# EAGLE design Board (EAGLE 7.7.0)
Assembly variants: PASTE

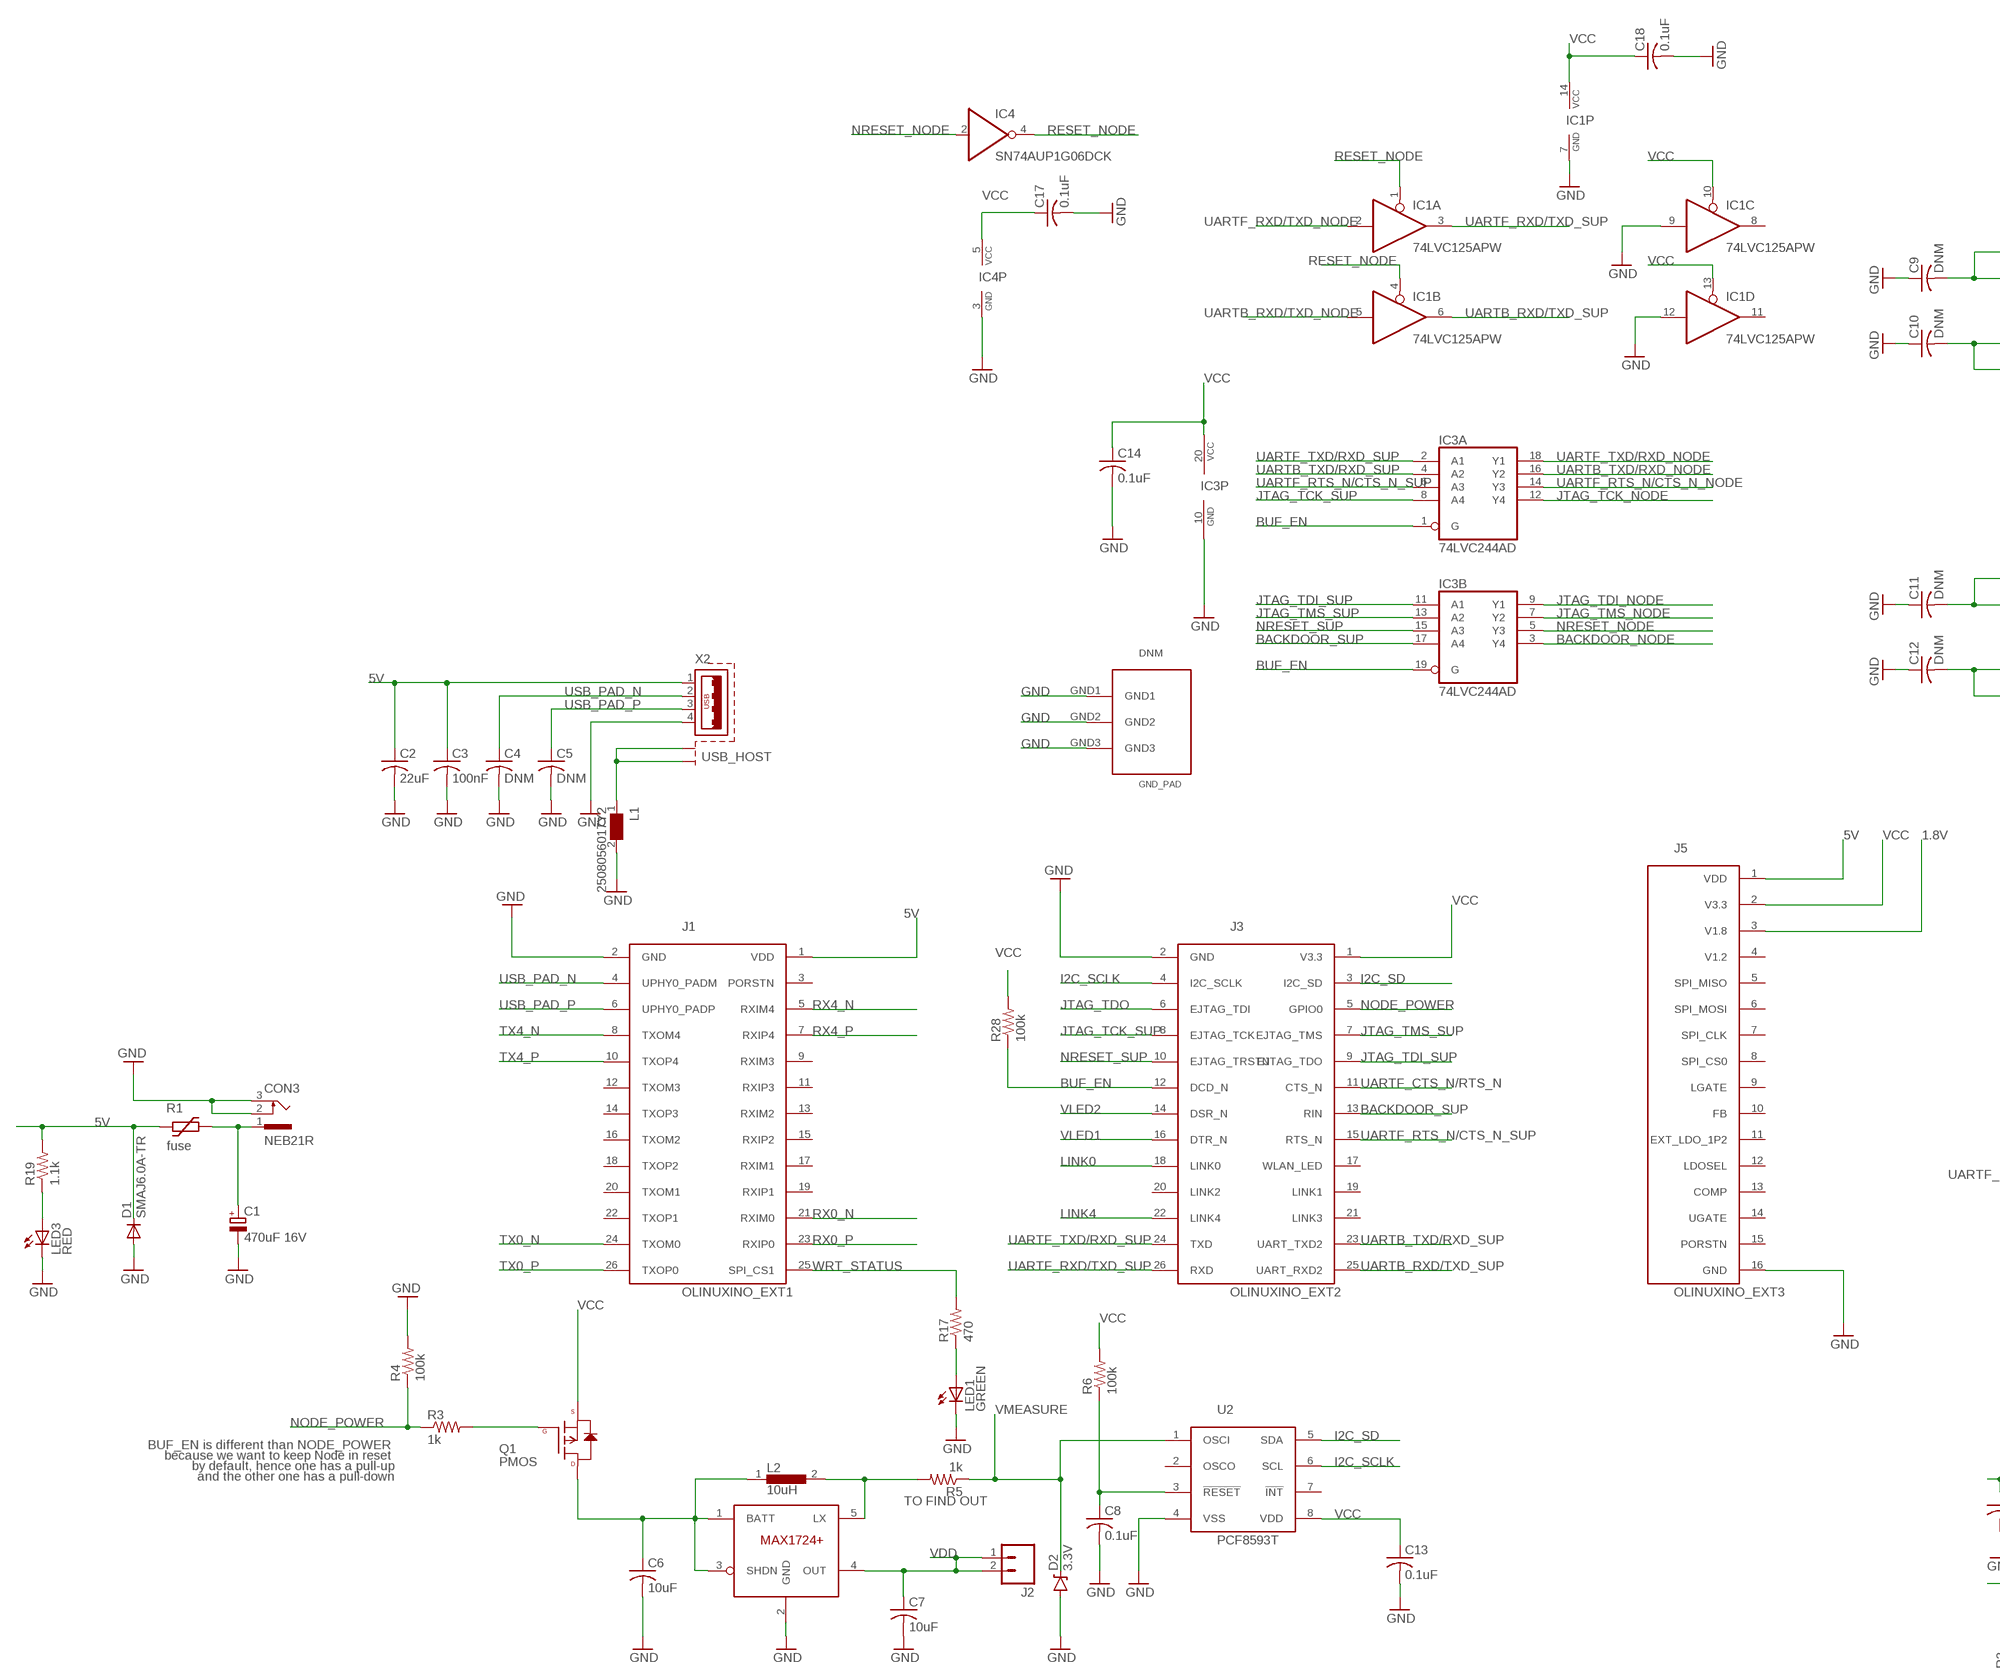
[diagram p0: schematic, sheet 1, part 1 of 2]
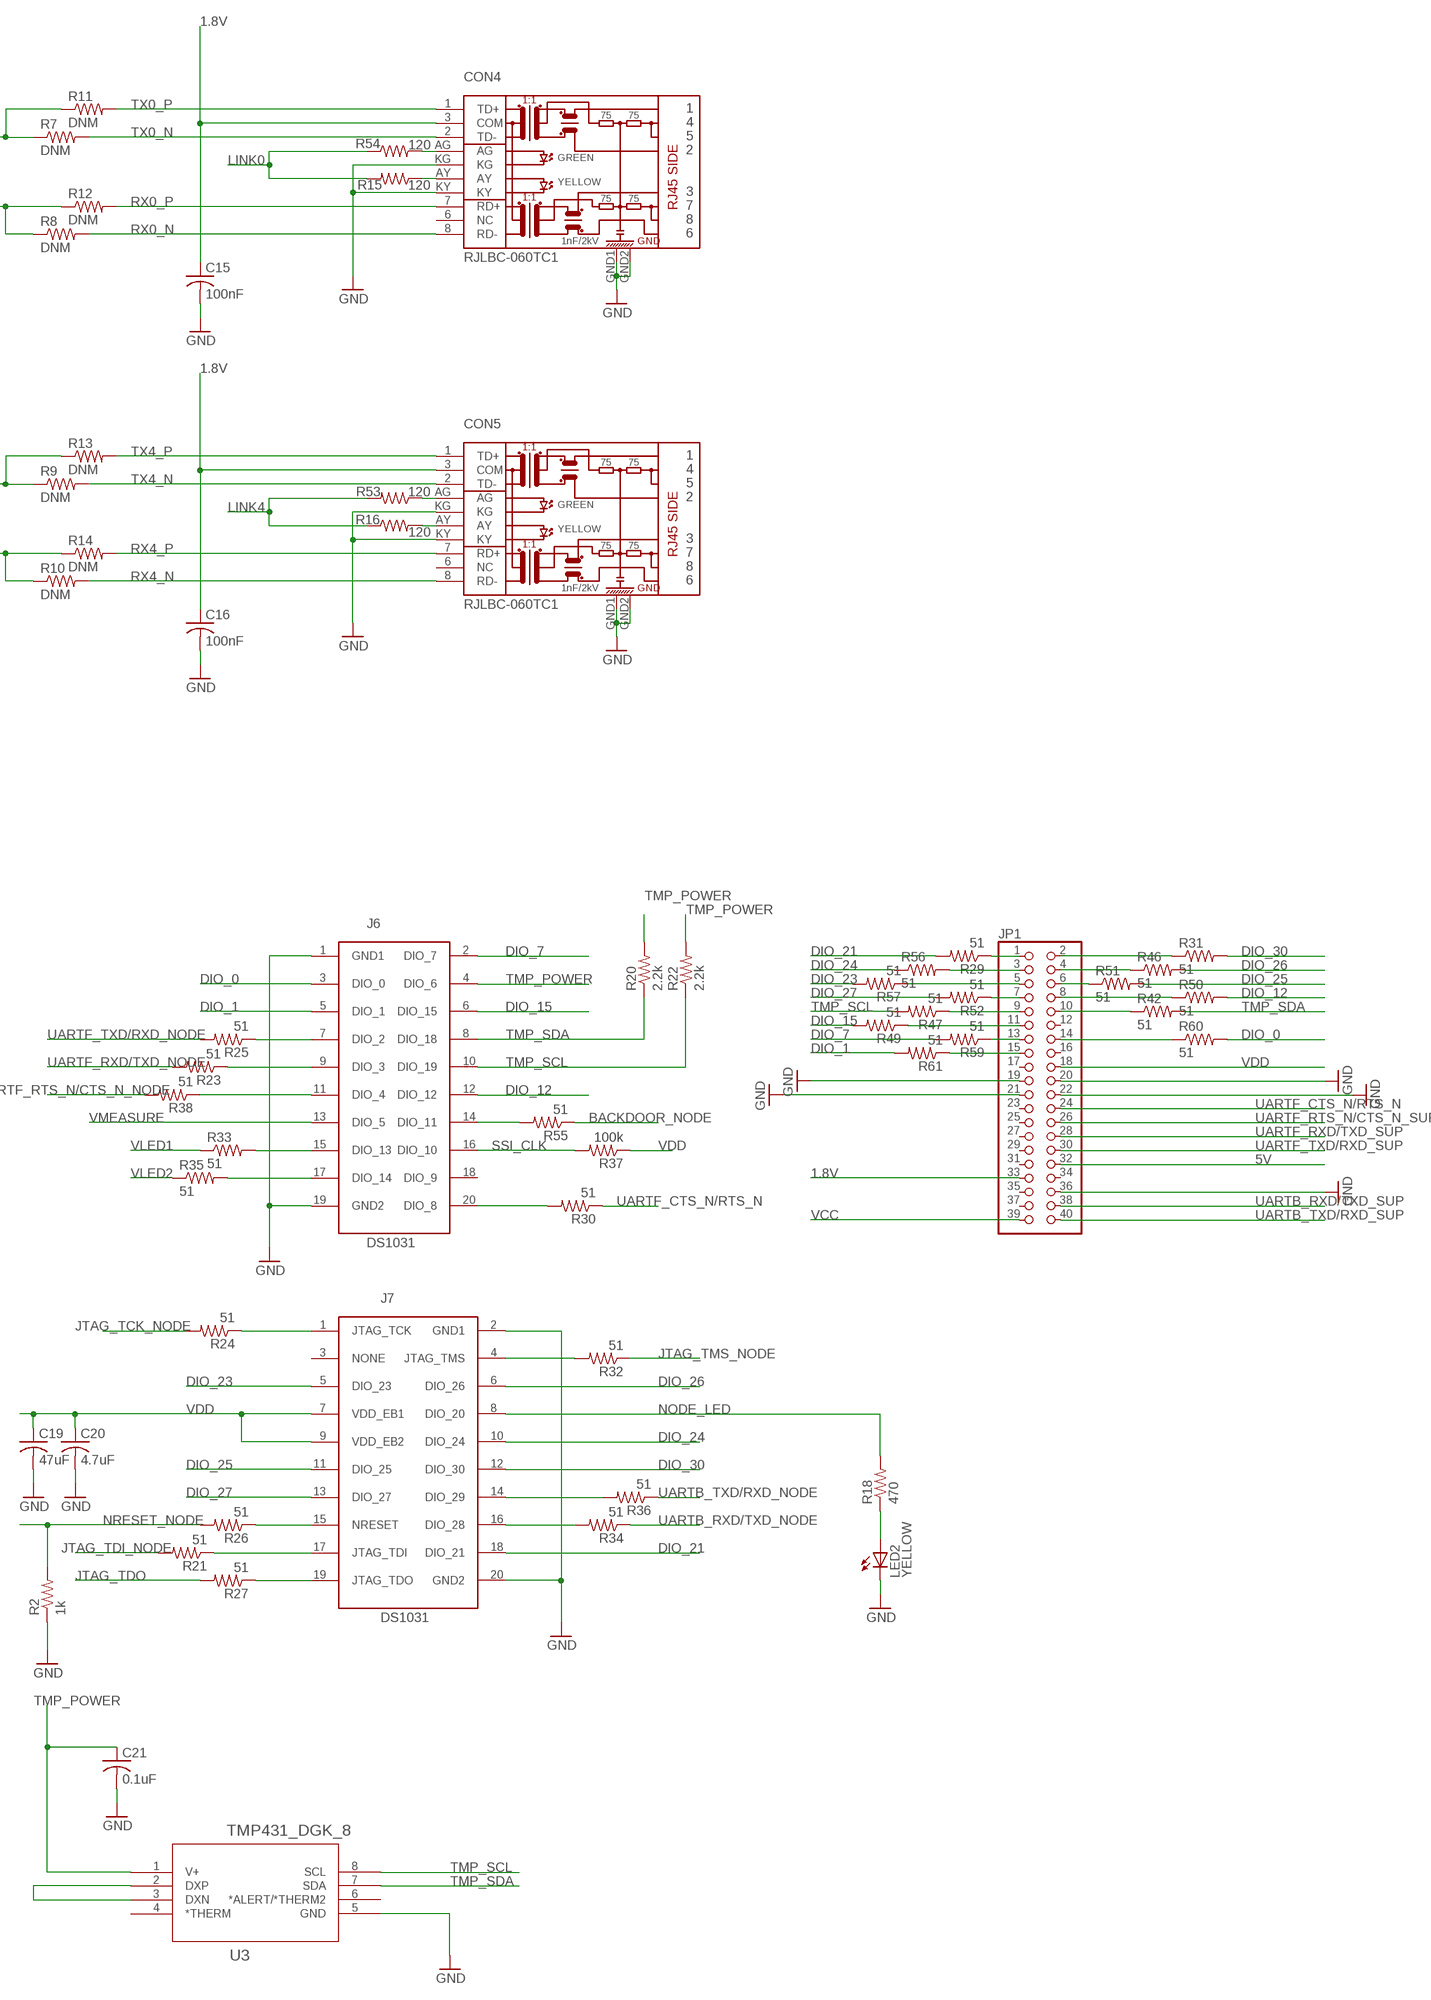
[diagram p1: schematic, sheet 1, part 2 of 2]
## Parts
C1  470uF 16V  CPOL-EU153CLV-0810  [153CLV-0810]
C2  22uF  C-USC0603  [C0603]
C3  100nF  C-USC0603  [C0603]
C4  DNM  C-USC0603  [C0603]
C5  DNM  C-USC0603  [C0603]
C6  10uF  C-USC0603  [C0603]
C7  10uF  C-USC0603  [C0603]
C8  0.1uF  C-USC0603  [C0603]
C9  DNM  C-USC0603  [C0603]
C10  DNM  C-USC0603  [C0603]
C11  DNM  C-USC0603  [C0603]
C12  DNM  C-USC0603  [C0603]
C13  0.1uF  C-USC0603  [C0603]
C14  0.1uF  C-USC0603  [C0603]
C15  100nF  C-USC0603  [C0603]
C16  100nF  C-USC0603  [C0603]
C17  0.1uF  C-USC0603  [C0603]
C18  0.1uF  C-USC0603  [C0603]
C19  47uF  C-USC1206  [C1206]
C20  4.7uF  C-USC0603  [C0603]
C21  0.1uF  C-USC0603  [C0603]
CON3  NEB21R  [NEB21R]
CON4  RJLBC-060TC1  RJLBC-060TC1_GND  [RJLBC-060TC1]
CON5  RJLBC-060TC1  RJLBC-060TC1_GND  [RJLBC-060TC1]
D1  SMAJ6.0A-TR  DIODE-DO214AC  [DO214AC]
D2  3.3V  DIODE-ZENER3.3V  [SOD-323]
GND_PAD  DNM  GND_PAD  [GND_PAD]  (not fitted in variant PASTE)
IC1  74LVC125APW  74ABT125PW  [TSSOP14]
IC3  74LVC244AD  74LS244DW  [SO20W]
IC4  SN74AUP1G06DCK  74AUC1G06DCK  [SC70-5]
J1  OLINUXINO_EXT1  [SSW-113-02-S-D]
J2  M02PTH  [1X02]
J3  OLINUXINO_EXT2  [SSW-113-02-S-D]
J5  OLINUXINO_EXT3  [SSW-116-02-S-S]
J6  DS1031  CC2650_EM1  [DS1031-08-2*10P8BS-4-1]
J7  DS1031  CC2650_EM2  [DS1031-08-2*10P8BS-4-1]
JP1  PINHD-2X20-BIG  [2X20-BIG]
L1  2508056017Y2  WE-CBF_0805  [0805]
L2  10uH  CR32  [CR32]
LED1  GREEN  LED3MM  [LED3MM]
LED2  YELLOW  LED3MM  [LED3MM]
LED3  RED  LED3MM  [LED3MM]
Q1  PMOS  P-CHANNEL-MOSFET  [SOT23-3]
R1  fuse  SD125-06  [1812]
R2  1k  RESISTOR0603  [0603-RES]
R3  1k  RESISTOR0603  [0603-RES]
R4  100k  RESISTOR0603  [0603-RES]
R5  1k  RESISTOR0603  [0603-RES]
R6  100k  RESISTOR0603  [0603-RES]
R7  DNM  RESISTOR0603  [0603-RES]
R8  DNM  RESISTOR0603  [0603-RES]
R9  DNM  RESISTOR0603  [0603-RES]
R10  DNM  RESISTOR0603  [0603-RES]
R11  DNM  RESISTOR0603  [0603-RES]
R12  DNM  RESISTOR0603  [0603-RES]
R13  DNM  RESISTOR0603  [0603-RES]
R14  DNM  RESISTOR0603  [0603-RES]
R15  120  RESISTOR0603  [0603-RES]
R16  120  RESISTOR0603  [0603-RES]
R17  470  RESISTOR0603  [0603-RES]
R18  470  RESISTOR0603  [0603-RES]
R19  1.1k  RESISTOR0603  [0603-RES]
R20  2.2k  RESISTOR0603  [0603-RES]
R21  51  RESISTOR0603  [0603-RES]
R22  2.2k  RESISTOR0603  [0603-RES]
R23  51  RESISTOR0603  [0603-RES]
R24  51  RESISTOR0603  [0603-RES]
R25  51  RESISTOR0603  [0603-RES]
R26  51  RESISTOR0603  [0603-RES]
R27  51  RESISTOR0603  [0603-RES]
R28  100k  RESISTOR0603  [0603-RES]
R29  51  RESISTOR0603  [0603-RES]
R30  51  RESISTOR0603  [0603-RES]
R31  51  RESISTOR0603  [0603-RES]
R32  51  RESISTOR0603  [0603-RES]
R33  51  RESISTOR0603  [0603-RES]
R34  51  RESISTOR0603  [0603-RES]
R35  51  RESISTOR0603  [0603-RES]
R36  51  RESISTOR0603  [0603-RES]
R37  100k  RESISTOR0603  [0603-RES]
R38  51  RESISTOR0603  [0603-RES]
R42  51  RESISTOR0603  [0603-RES]
R46  51  RESISTOR0603  [0603-RES]
R47  51  RESISTOR0603  [0603-RES]
R49  51  RESISTOR0603  [0603-RES]
R50  51  RESISTOR0603  [0603-RES]
R51  51  RESISTOR0603  [0603-RES]
R52  51  RESISTOR0603  [0603-RES]
R53  120  RESISTOR0603  [0603-RES]
R54  120  RESISTOR0603  [0603-RES]
R55  51  RESISTOR0603  [0603-RES]
R56  51  RESISTOR0603  [0603-RES]
R57  51  RESISTOR0603  [0603-RES]
R59  51  RESISTOR0603  [0603-RES]
R60  51  RESISTOR0603  [0603-RES]
R61  51  RESISTOR0603  [0603-RES]
U1  MAX1724  [SOT23-5L]
U2  PCF8593T  [SO-08]
U3  TMP431_DGK_8  [DGK8]
X2  USB_HOST  TUEA4F2S0BHT  [TUEA4F2S0BHT]

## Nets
1.8V [supply]: C15.1 C16.1 CON4.3(COM) CON5.3(COM) J5.3(V1.8) JP1.33
5V [supply]: C2.1 C3.1 D1.C J1.1(VDD) J5.1(VDD) JP1.32 R1.P$1 R19.2 X2.1(VCC)
BACKDOOR_NODE: IC3.3(B:Y4) R55.1
BACKDOOR_SUP: IC3.17(B:A4) J3.13(RIN)
BATT [supply]: C6.1 L2.1 Q1.3(D) U1.1(BATT) U1.3(SHDN)
BUF_EN: IC3.1(A:G) IC3.19(B:G) J3.12(DCD_N) R28.1
COUNTER [supply]: L2.2 R5.2 U1.5(LX)
DIO_0: J6.3(DIO_0) R60.2
DIO_1: J6.5(DIO_1) R61.2
DIO_7: J6.2(DIO_7) R59.2
DIO_12: J6.12(DIO_12) R50.2
DIO_15: J6.6(DIO_15) R49.2
DIO_21: J7.18(DIO_21) R29.2
DIO_23: J7.5(DIO_23) R57.2
DIO_24: J7.10(DIO_24) R56.1
DIO_25: J7.11(DIO_25) R51.2
DIO_26: J7.6(DIO_26) R46.2
DIO_27: J7.13(DIO_27) R52.2
DIO_30: J7.12(DIO_30) R31.2
GND [supply]: C1.- C2.2 C3.2 C4.2 C5.2 C6.2 C7.2 C8.2 C9.1 C10.1 C11.1 C12.1 C13.2 C14.2 C15.2 C16.2 C17.2 C18.2 C19.2 C20.2 C21.2 CON3.2 CON3.3 CON4.GND1 CON4.GND2 CON4.KG CON4.KY CON5.GND1 CON5.GND2 CON5.KG CON5.KY D1.A D2.A GND_PAD.GND1 GND_PAD.GND2 GND_PAD.GND3 IC1.7(P:GND) IC1.9(C:I) IC1.12(D:I) IC3.10(P:GND) IC4.3(GND) J1.2(GND) J3.2(GND) J5.16(GND) J6.1(GND1) J6.19(GND2) J7.2(GND1) J7.20(GND2) JP1.19 JP1.20 JP1.21 JP1.22 JP1.36 L1.2 LED1.K(C) LED2.K(C) LED3.K(C) R2.1 R4.2 U1.2(GND) U2.4(VSS) U3.5(GND) X2.4(GND)
I2C_SCLK: J3.4(I2C_SCLK) U2.6(SCL)
I2C_SD: J3.3(I2C_SD) U2.5(SDA)
JTAG_TCK_NODE: IC3.12(A:Y4) R24.2
JTAG_TCK_SUP: IC3.8(A:A4) J3.8(EJTAG_TCK)
JTAG_TDI_NODE: IC3.9(B:Y1) R21.2
JTAG_TDI_SUP: IC3.11(B:A1) J3.9(EJTAG_TDO)
JTAG_TDO: J3.6(EJTAG_TDI) R27.2
JTAG_TMS_NODE: IC3.7(B:Y2) R32.1
JTAG_TMS_SUP: IC3.13(B:A2) J3.7(EJTAG_TMS)
LINK0: J3.18(LINK0) R15.2 R54.1
LINK4: J3.22(LINK4) R16.1 R53.2
N$1: CON4.AG R54.2
N$2: Q1.1(G) R3.2
N$3: C12.2 R10.1 R14.1
N$4: C11.2 R9.1 R13.1
N$13: CON5.AY R16.2
N$14 [supply]: L1.1 X2.S1 X2.S2
N$15: J7.4(JTAG_TMS) R32.2
N$18: J7.1(JTAG_TCK) R24.1
N$19: C10.2 R8.1 R12.1
N$20: J7.15(NRESET) R26.1
N$21: C9.2 R7.1 R11.1
N$22: J7.17(JTAG_TDI) R21.1
N$23: J7.19(JTAG_TDO) R27.1
N$24: J6.7(DIO_2) R25.1
N$25: J6.9(DIO_3) R23.1
N$26: JP1.1 R29.1
N$27: CON4.AY R15.1
N$28: J6.20(DIO_8) R30.2
N$29: LED1.A R17.1
N$30: LED2.A R18.1
N$31: J6.14(DIO_11) R55.2
N$32: C1.+ CON3.1 R1.P$2
N$33: CON5.AG R53.1
N$34: C8.1 R6.1 U2.3(!RESET)
N$35: J6.15(DIO_13) R33.2
N$36: JP1.2 R31.1
N$37: JP1.3 R56.2
N$38: J6.17(DIO_14) R35.2
N$40: JP1.4 R46.1
N$41: JP1.5 R57.1
N$42: JP1.6 R51.1
N$43: JP1.7 R52.1
N$44: JP1.8 R50.1
N$45: JP1.9 R47.1
N$46: JP1.10 R42.1
N$47: JP1.11 R49.1
N$49: U3.2(DXP) U3.3(DXN)
N$50: LED3.A R19.1
N$65: JP1.13 R59.1
N$66: J7.14(DIO_29) R36.2
N$67: J7.16(DIO_28) R34.2
N$68: JP1.14 R60.1
N$69: JP1.15 R61.1
N$72: J6.11(DIO_4) R38.1
NODE_LED: J7.8(DIO_20) R18.2
NODE_POWER: J3.5(GPIO0) R3.1 R4.1
NRESET_NODE: IC3.5(B:Y3) IC4.2(I) R2.2 R26.2
NRESET_SUP: IC3.15(B:A3) J3.10(EJTAG_TRSTN)
RESET_NODE: IC1.1(A:OE) IC1.4(B:OE) IC4.4(O)
RX0_N: CON4.8(RD-) J1.21(RXIM0) R8.2
RX0_P: CON4.7(RD+) J1.23(RXIP0) R12.2
RX4_N: CON5.8(RD-) J1.5(RXIM4) R10.2
RX4_P: CON5.7(RD+) J1.7(RXIP4) R14.2
SSI_CLK: J6.16(DIO_10) R37.2
TMP_POWER [supply]: C21.1 J6.4(DIO_6) R20.2 R22.2 U3.1(V+)
TMP_SCL: J6.10(DIO_19) R22.1 R47.2 U3.8(SCL)
TMP_SDA: J6.8(DIO_18) R20.1 R42.2 U3.7(SDA)
TX0_N: CON4.2(TD-) J1.24(TXOM0) R7.2
TX0_P: CON4.1(TD+) J1.26(TXOP0) R11.2
TX4_N: CON5.2(TD-) J1.8(TXOM4) R9.2
TX4_P: CON5.1(TD+) J1.10(TXOP4) R13.2
UARTB_RXD/TXD_NODE: IC1.5(B:I) R34.1
UARTB_RXD/TXD_SUP: IC1.6(B:O) J3.25(UART_RXD2) JP1.38
UARTB_TXD/RXD_NODE: IC3.16(A:Y2) R36.1
UARTB_TXD/RXD_SUP: IC3.4(A:A2) J3.23(UART_TXD2) JP1.40
UARTF_CTS_N/RTS_N: J3.11(CTS_N) JP1.24 R30.1
UARTF_RTS_N/CTS_N_NODE: IC3.14(A:Y3) R38.2
UARTF_RTS_N/CTS_N_SUP: IC3.6(A:A3) J3.15(RTS_N) JP1.26
UARTF_RXD/TXD_NODE: IC1.2(A:I) R23.2
UARTF_RXD/TXD_SUP: IC1.3(A:O) J3.26(RXD) JP1.28
UARTF_TXD/RXD_NODE: IC3.18(A:Y1) R25.2
UARTF_TXD/RXD_SUP: IC3.2(A:A1) J3.24(TXD) JP1.30
USB_PAD_N: C4.1 J1.4(UPHY0_PADM) X2.2(D-)
USB_PAD_P: C5.1 J1.6(UPHY0_PADP) X2.3(D+)
VCC [supply]: C13.1 C14.1 C17.1 C18.1 IC1.10(C:OE) IC1.13(D:OE) IC1.14(P:VCC) IC3.20(P:VCC) IC4.5(VCC) J3.1(V3.3) J5.2(V3.3) JP1.39 Q1.2(S) R6.2 R28.2 U2.8(VDD)
VDD [supply]: C7.1 C19.1 C20.1 J2.1 J2.2 J7.7(VDD_EB1) J7.9(VDD_EB2) JP1.18 R37.1 U1.4(OUT)
VLED1: J3.16(DTR_N) R33.1
VLED2: J3.14(DSR_N) R35.1
VMEASURE: D2.C J6.13(DIO_5) R5.1 U2.1(OSCI)
WRT_STATUS: J1.25(SPI_CS1) R17.2
Unconnected: CON4.6(NC) CON5.6(NC) IC1.8(C:O) IC1.11(D:O) J1.3(PORSTN) J1.9(RXIM3) J1.11(RXIP3) J1.12(TXOM3) J1.13(RXIM2) J1.14(TXOP3) J1.15(RXIP2) J1.16(TXOM2) J1.17(RXIM1) J1.18(TXOP2) J1.19(RXIP1) J1.20(TXOM1) J1.22(TXOP1) J3.17(WLAN_LED) J3.19(LINK1) J3.20(LINK2) J3.21(LINK3) J5.4(V1.2) J5.5(SPI_MISO) J5.6(SPI_MOSI) J5.7(SPI_CLK) J5.8(SPI_CS0) J5.9(LGATE) J5.10(FB) J5.11(EXT_LDO_1P2) J5.12(LDOSEL) J5.13(COMP) J5.14(UGATE) J5.15(PORSTN) J6.18(DIO_9) J7.3(NONE) JP1.12 JP1.16 JP1.17 JP1.23 JP1.25 JP1.27 JP1.29 JP1.31 JP1.34 JP1.35 JP1.37 U2.2(OSCO) U2.7(!INT) U3.4(*THERM) U3.6(*ALERT/*THERM2)

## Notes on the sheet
- BUF_EN is different than NODE_POWER 
  because we want to keep Node in reset 
  by default, hence one has a pull-up
  and the other one has a pull-down
- TO FIND OUT

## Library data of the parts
C1 = resistor:CPOL-EU: POLARIZED CAPACITOR, European symbol
C2-C21 = adafruit:C-US: CAPACITOR, American symbol
CON3 = con-lumberg:NEB21R: Netzgeräte-Einbaukupplung abgewinkelte Ausführung mit Öffner Source: http://www.lumberg.com/Produkte/PDFs/NEB21R.pdf; MPN: NEB 21 R; OC_FARNELL: 1217037; OC_NEWARK: 97K6458
CON4 CON5 = RT5350F_OLinuXino_EVB_Rev_A:RJLBC-060TC1_GND
D1 = diode:DIODE-: DIODE
D2 = SparkFun-DiscreteSemi:DIODE-ZENER: Zener Diode; PROD_ID: DIO-11284
GND_PAD = heni-lib:GND_PAD
IC1 = 74xx-eu:74*125: Quad bus BUFFER, 3-state
IC3 = 74xx-us:74*244: Octal BUFFER and LINE DRIVER, 3-state
IC4 = 74xx-little-de:74*1G06: Single Inverter Buffer/Driver With Open-Drain Output
J1 = heni-lib:OLINUXINO_EXT1
J2 = SparkFun-Connectors:M02: Standard 2-pin 0.1" header. Use with
J3 = heni-lib:OLINUXINO_EXT2
J5 = heni-lib:OLINUXINO_EXT3
J6 = heni-lib:CC2650_EM1
J7 = heni-lib:CC2650_EM2
JP1 = adafruit:PINHD-2X20: PIN HEADER
L1 = Wuerth_Elektronik_eiSos_V6:WE-CBF: SMD EMI Suppression Ferrite Beads WE-CBF
L2 = inductors:CR32: POWER INDUCTORS SMD CR Series
LED1-LED3 = adafruit:LED: LED
Q1 = GeekAmmo:P-CHANNEL-MOSFET: P-Channel MOSFET Mode Field Effect Transistor
R1 = heni-lib:SD125-06
R2-R38 R42 R46 R47 R49-R57 R59-R61 = SparkFun-Resistors:RESISTOR: Resistor
U1 = MAX1724:MAX1724
U2 = heni-lib:PCF8593T
U3 = TMP431:TMP431_DGK_8; DATASHEETURL: http://www.ti.com/lit/gpn/TMP431; DESCRIPTION: +/-1°C Remote and Local Temperature Sensor with Beta, N-Factor and Series-R Correction; FAMILY_NAME: TEMPERATURE SENSOR; GENERIC_PART_NUMBER: TMP431; INDUSTRY_STD_PKG_TYPE: MSOP; MANUFACTURER: Texas Instruments; MANUFACTURER_PART_NUMBER: tmp431_dgk_8; PACKAGE_DESIGNATOR: DGK; PIN_COUNT: 8; VENDOR: Texas Instruments
X2 = heni-lib:TUEA4F2S0BHT

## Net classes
0 default: width 0.203 mm
1 supply: width 0.508 mm

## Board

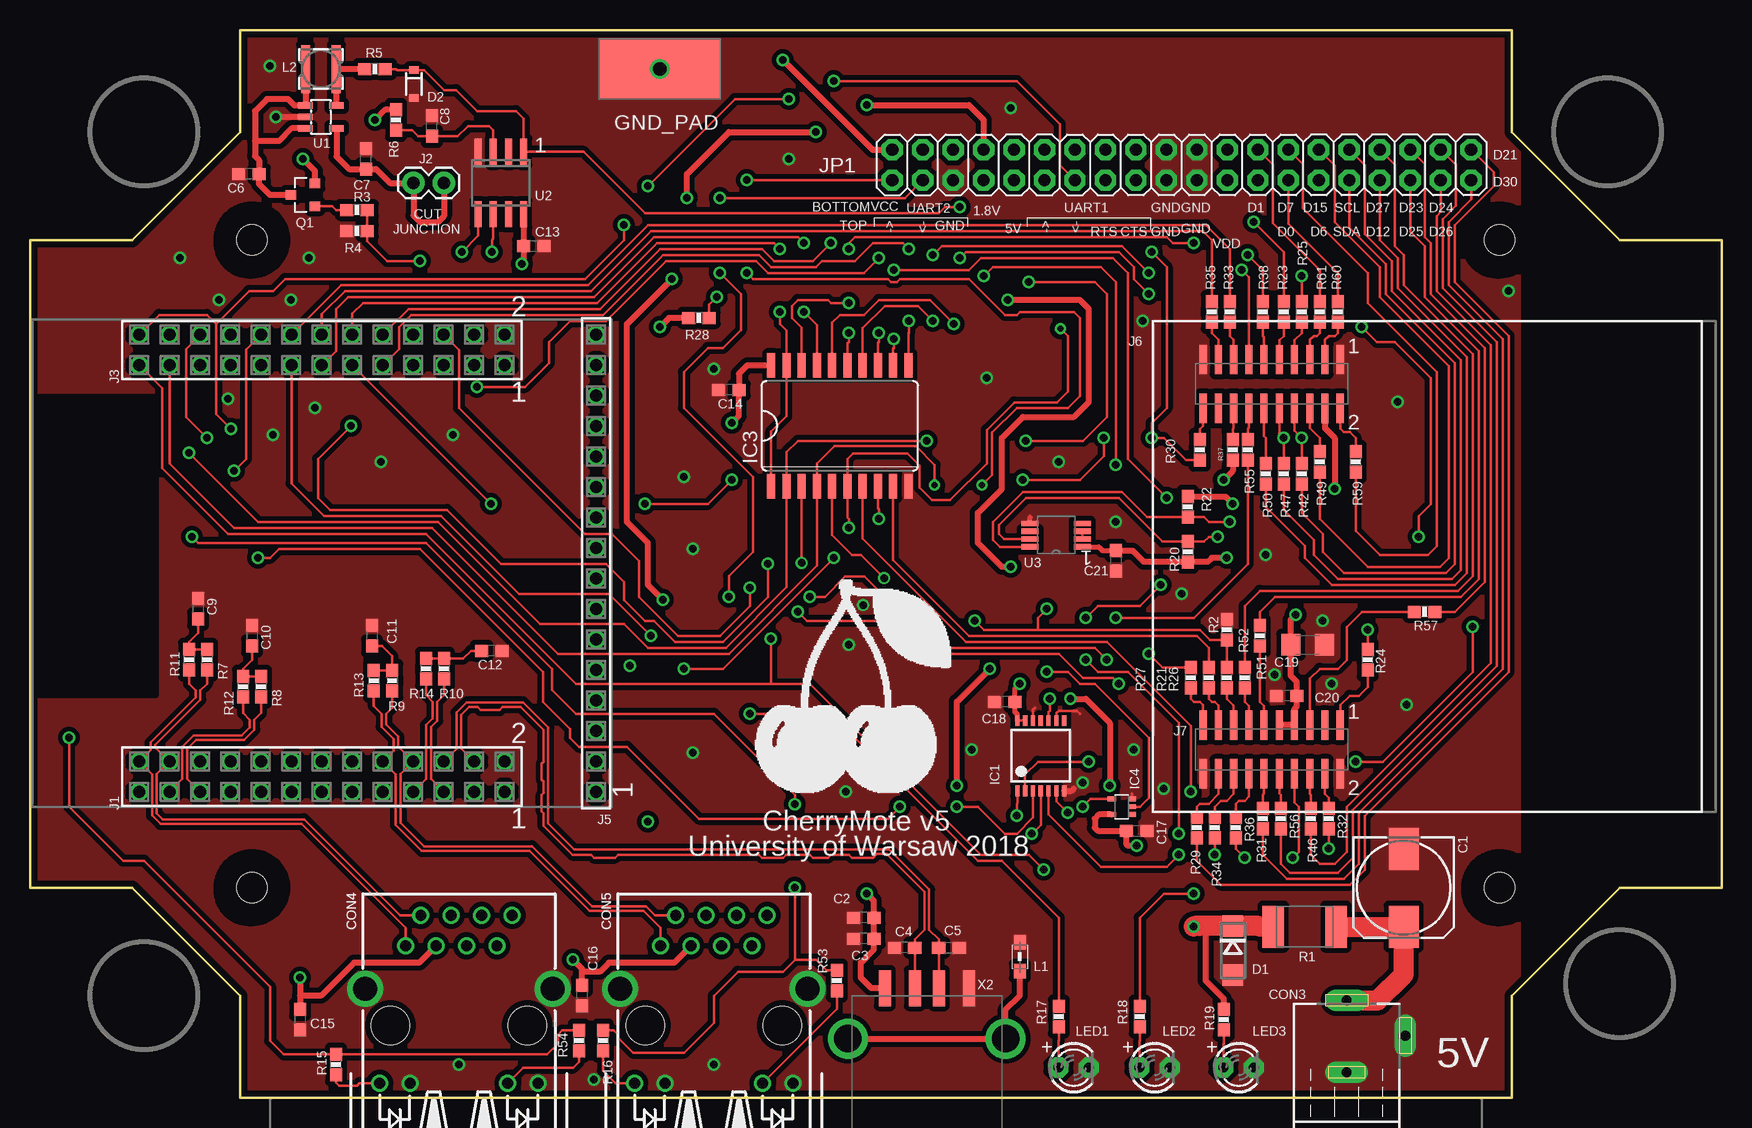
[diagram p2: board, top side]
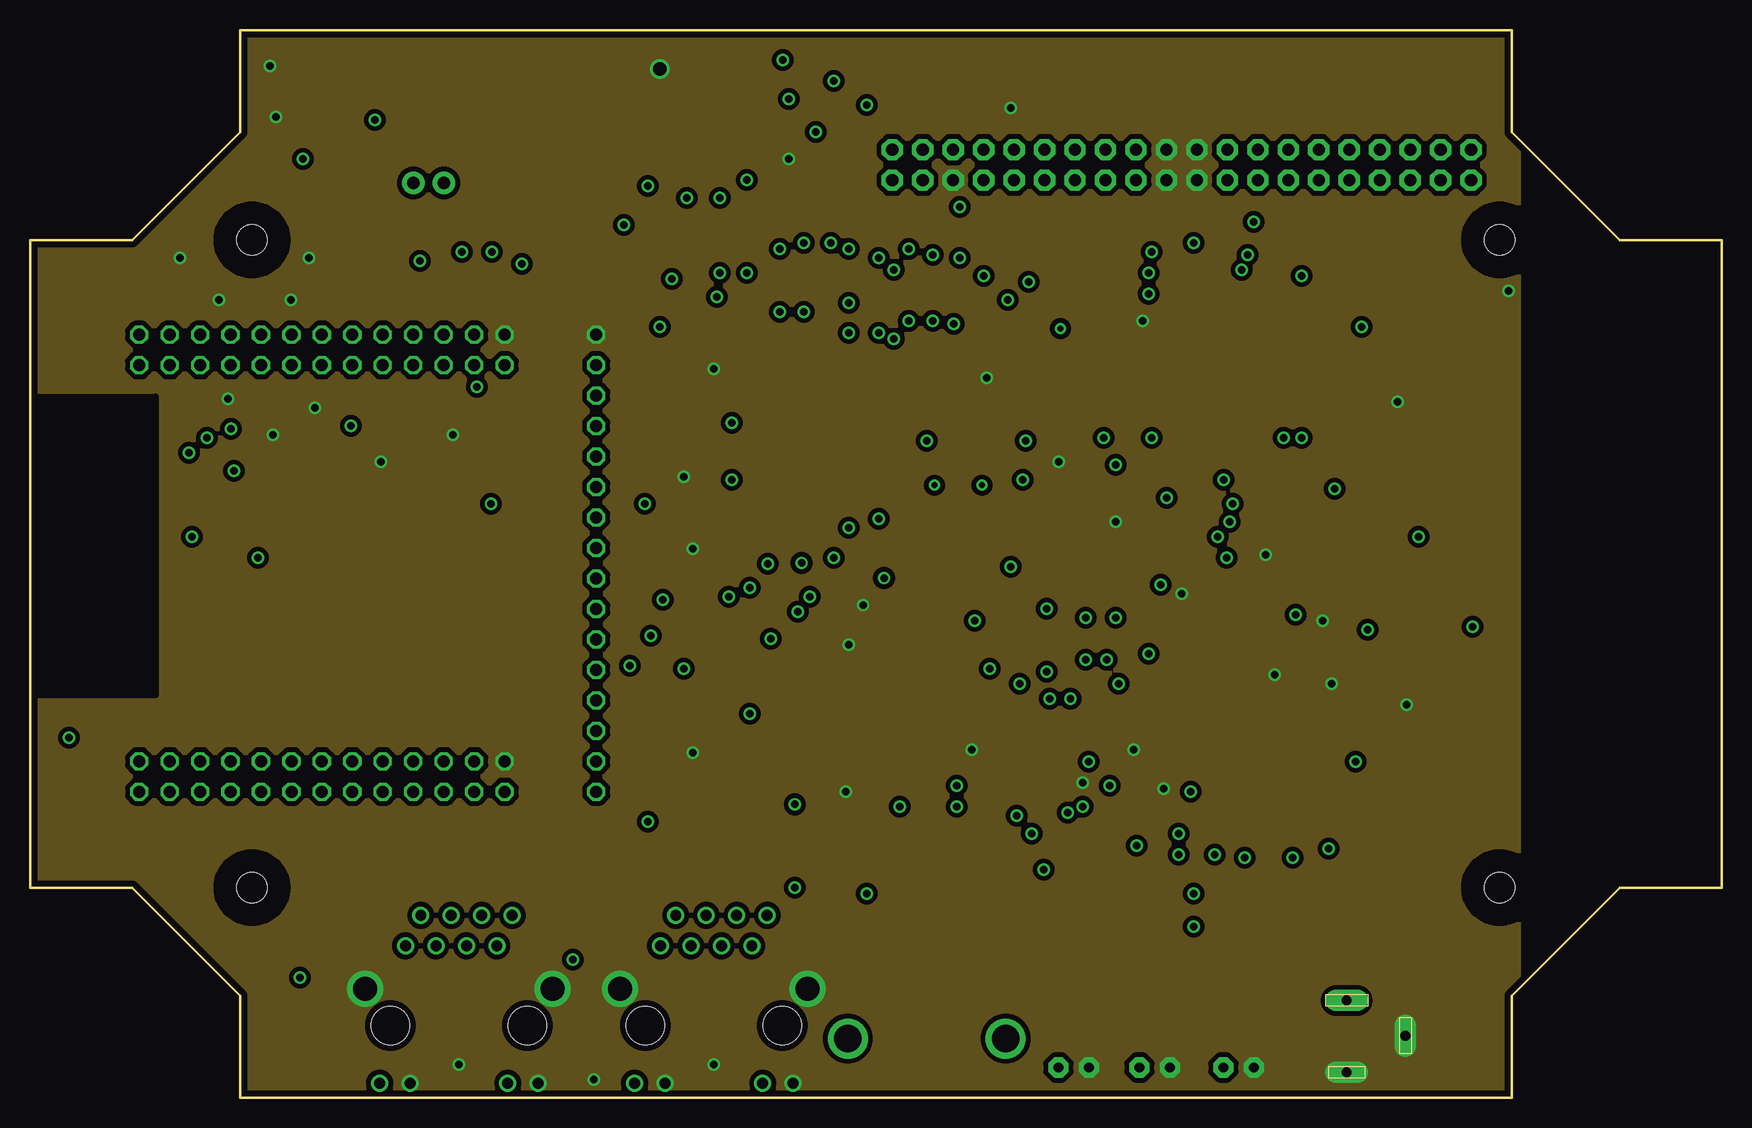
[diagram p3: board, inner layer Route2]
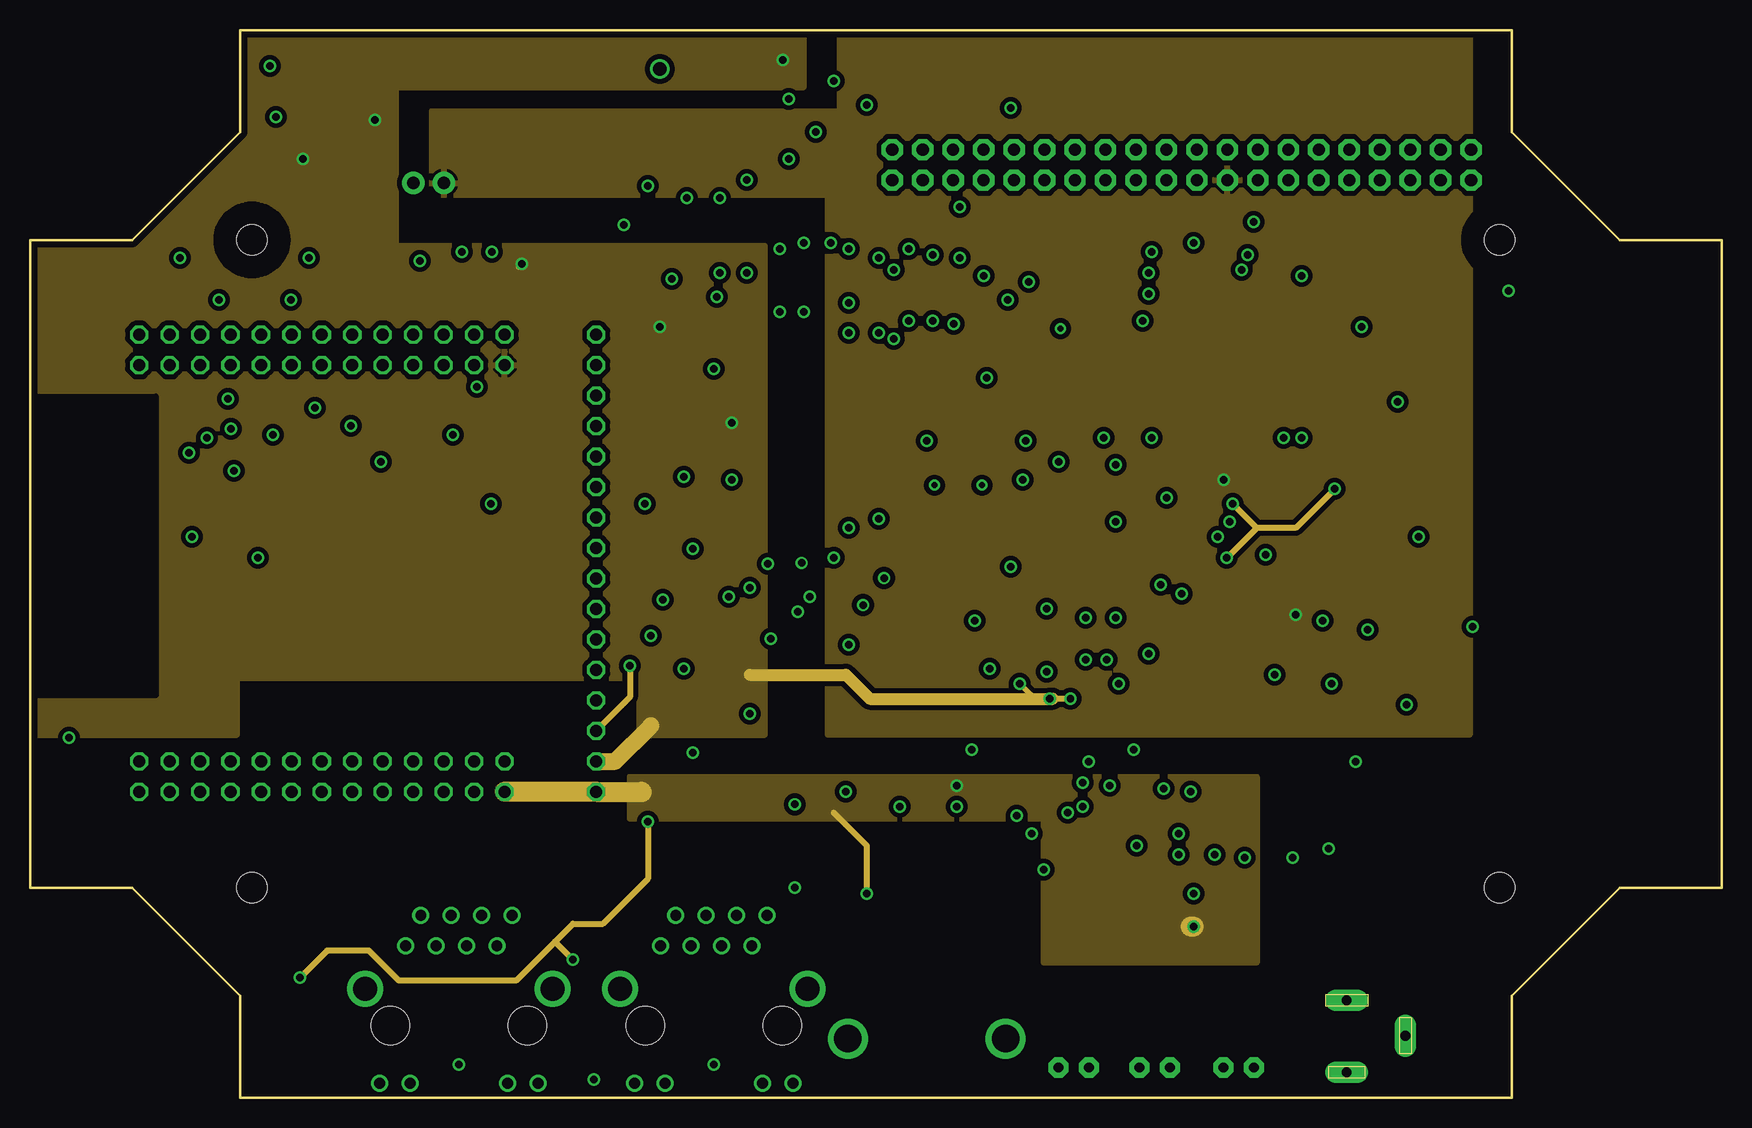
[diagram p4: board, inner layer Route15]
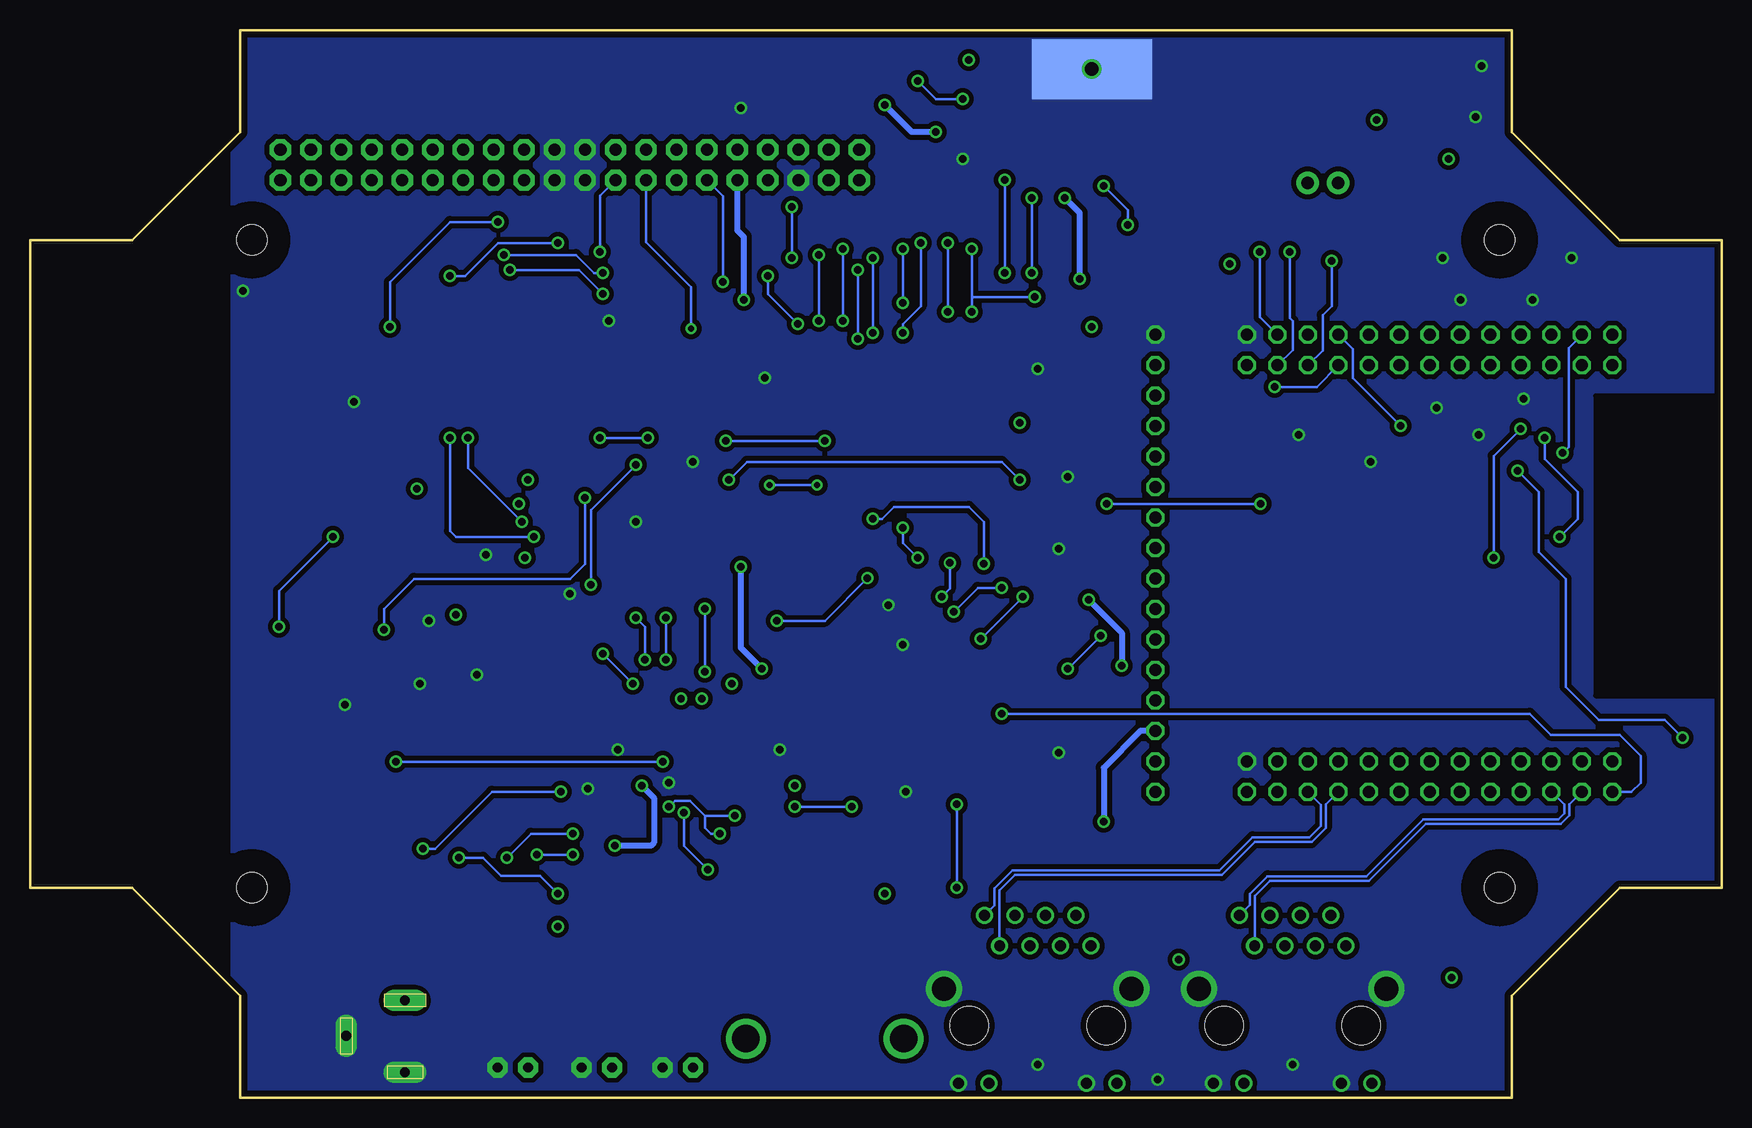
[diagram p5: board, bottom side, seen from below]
Size 141 x 89 mm. Coordinates in mm from the lower left corner, seen from the top.
Outline: 141,17.5 141,71.5 132.5,71.5 123.5,80.5 123.5,89 17.5,89 17.5,80.5 8.5,71.5 0,71.5 0,17.5 8.5,17.5 17.5,8.5 17.5,0 123.5,0 123.5,8.5 132.5,17.5 141,17.5
Copper layers (1*2*15*16): Top 0.018mm / dielectric 15mil / Route2 0.035mm / dielectric 0.709mm / Route15 0.035mm / dielectric 15mil / Bottom 0.018mm
Design rules "box": minimum track width 8mil, minimum drill 20mil, track to track 8mil, track to pad 8mil, pad to pad 8mil, via to via 8mil, smd to smd 8mil, copper to edge 20mil, drill to drill 8mil, minimum pad ring 10mil, minimum via ring 8mil, stop-mask expansion 2mil, vias tented up to drill 0mil, thermal gap 10mil
Holes 2.5 mm at 18.5,71.5 122.5,71.5 122.5,17.5 18.5,17.5

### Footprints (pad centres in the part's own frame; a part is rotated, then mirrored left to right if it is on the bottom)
153CLV-0810 = smd 3.5 x 2.5: + 3.25,0; - -3.25,0
C0603 = smd 1.1 x 1: 1 -0.85,0; 2 0.85,0
C1206 = smd 1.6 x 1.8: 1 -1.4,0; 2 1.4,0
NEB21R = drill 0.813 pad 1.778 long: 1 0,7.35; 2 4.9,4.4; 3 0,1.35
RJLBC-060TC1 = drill 0.9: 1 -4.445,6.65; 2 -3.175,9.19; 3 -1.905,6.65; 4 -0.635,9.19; 5 0.635,6.65; 6 1.905,9.19; 7 3.175,6.65; 8 4.445,9.19; AG 4.07,-4.8; AY -6.61,-4.8; KG 6.61,-4.8; KY -4.07,-4.8 | drill 2: GND1 -7.8,3.05; GND2 7.8,3.05 | hole 3.2: -5.715,0; 5.715,0; -5.715,0; 5.715,0
DO214AC = smd 1.8 x 1.7: A 2.05,0; C -2.05,0
SOD-323 = smd 0.63 x 0.83: A 1.15,0; C -1.15,0
GND_PAD = smd 10 x 5: GND1 0,0 | smd 10 x 5 bottom: GND2 0,0 | drill 1.1: GND3 0,0
TSSOP14 = smd 0.35 x 0.9: 1 -1.95,-2.925; 2 -1.3,-2.925; 3 -0.65,-2.925; 4 0,-2.925; 5 0.65,-2.925; 6 1.3,-2.925; 7 1.95,-2.925; 8 1.95,2.925; 9 1.3,2.925; 10 0.65,2.925; 11 0,2.925; 12 -0.65,2.925; 13 -1.3,2.925; 14 -1.95,2.925
SO20W = smd 0.66 x 2.032: 1 -5.715,-5.029; 2 -4.445,-5.029; 3 -3.175,-5.029; 4 -1.905,-5.029; 5 -0.635,-5.029; 6 0.635,-5.029; 7 1.905,-5.029; 8 3.175,-5.029; 9 4.445,-5.029; 10 5.715,-5.029; 11 5.715,5.029; 12 4.445,5.029; 13 3.175,5.029; 14 1.905,5.029; 15 0.635,5.029; 16 -0.635,5.029; 17 -1.905,5.029; 18 -3.175,5.029; 19 -4.445,5.029; 20 -5.715,5.029
SC70-5 = smd 0.4 x 0.7: 1 -0.65,-0.85; 2 0,-0.85; 3 0.65,-0.85; 4 0.65,0.85; 5 -0.65,0.85
SSW-113-02-S-D = drill 1 pad 1.5 octagon: 1 15.24,-1.27; 2 15.24,1.27; 3 12.7,-1.27; 4 12.7,1.27; 5 10.16,-1.27; 6 10.16,1.27; 7 7.62,-1.27; 8 7.62,1.27; 9 5.08,-1.27; 10 5.08,1.27; 11 2.54,-1.27; 12 2.54,1.27; 13 0,-1.27; 14 0,1.27; 15 -2.54,-1.27; 16 -2.54,1.27; 17 -5.08,-1.27; 18 -5.08,1.27; 19 -7.62,-1.27; 20 -7.62,1.27; 21 -10.16,-1.27; 22 -10.16,1.27; 23 -12.7,-1.27; 24 -12.7,1.27; 25 -15.24,-1.27; 26 -15.24,1.27
1X02 = drill 1.016 pad 1.88: 1 0,0; 2 2.54,0
SSW-116-02-S-S = drill 1 pad 1.5 octagon: 1 -19.05,0; 2 -16.51,0; 3 -13.97,0; 4 -11.43,0; 5 -8.89,0; 6 -6.35,0; 7 -3.81,0; 8 -1.27,0; 9 1.27,0; 10 3.81,0; 11 6.35,0; 12 8.89,0; 13 11.43,0; 14 13.97,0; 15 16.51,0; 16 19.05,0
DS1031-08-2*10P8BS-4-1 = smd 0.6 x 2.45: 1 5.715,2.025; 2 5.715,-2.025; 3 4.445,2.025; 4 4.445,-2.025; 5 3.175,2.025; 6 3.175,-2.025; 7 1.905,2.025; 8 1.905,-2.025; 9 0.635,2.025; 10 0.635,-2.025; 11 -0.635,2.025; 12 -0.635,-2.025; 13 -1.905,2.025; 14 -1.905,-2.025; 15 -3.175,2.025; 16 -3.175,-2.025; 17 -4.445,2.025; 18 -4.445,-2.025; 19 -5.715,2.025; 20 -5.715,-2.025
2X20-BIG = drill 1.016 pad 1.778 octagon: 1 -24.13,-1.27; 2 -24.13,1.27; 3 -21.59,-1.27; 4 -21.59,1.27; 5 -19.05,-1.27; 6 -19.05,1.27; 7 -16.51,-1.27; 8 -16.51,1.27; 9 -13.97,-1.27; 10 -13.97,1.27; 11 -11.43,-1.27; 12 -11.43,1.27; 13 -8.89,-1.27; 14 -8.89,1.27; 15 -6.35,-1.27; 16 -6.35,1.27; 17 -3.81,-1.27; 18 -3.81,1.27; 19 -1.27,-1.27; 20 -1.27,1.27; 21 1.27,-1.27; 22 1.27,1.27; 23 3.81,-1.27; 24 3.81,1.27; 25 6.35,-1.27; 26 6.35,1.27; 27 8.89,-1.27; 28 8.89,1.27; 29 11.43,-1.27; 30 11.43,1.27; 31 13.97,-1.27; 32 13.97,1.27; 33 16.51,-1.27; 34 16.51,1.27; 35 19.05,-1.27; 36 19.05,1.27; 37 21.59,-1.27; 38 21.59,1.27; 39 24.13,-1.27; 40 24.13,1.27
0805 = smd 1.2 x 1: 1 -1.2,0; 2 1.2,0
CR32 = smd 0.75 x 4: 1 -1.275,0; 2 1.275,0
LED3MM = drill 0.813 pad 1.676 octagon: A -1.27,0; K 1.27,0
SOT23-3 = smd 0.8 x 0.9: 1 -0.95,-1; 2 0.95,-1; 3 0,1
1812 = smd 1.78 x 3.5: P$1 -2.615,0; P$2 2.615,0
0603-RES = smd 1.1 x 1: 1 -0.85,0; 2 0.85,0
SOT23-5L = smd 0.55 x 1.2: 1 -0.95,-1.3; 2 0,-1.3; 3 0.95,-1.3; 4 0.95,1.3; 5 -0.95,1.3
SO-08 = smd 0.6 x 2.2: 1 -1.905,-2.6; 2 -0.635,-2.6; 3 0.635,-2.6; 4 1.905,-2.6; 5 1.905,2.6; 6 0.635,2.6; 7 -0.635,2.6; 8 -1.905,2.6
DGK8 = smd 1.422 x 0.432: 1 -2.172,0.975; 2 -2.172,0.325; 3 -2.172,-0.325; 4 -2.172,-0.975; 5 2.172,-0.975; 6 2.172,-0.325; 7 2.172,0.325; 8 2.172,0.975
TUEA4F2S0BHT = smd 1 x 3: 1 -3.5,14.61; 2 -1,14.61; 3 1,14.61; 4 3.5,14.61 | drill 2.3: S1 -6.57,10.4; S2 6.57,10.4

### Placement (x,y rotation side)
C1  114.5,17.5 270 top
C2  69.5,15 180 top
C3  69.5,13.25 180 top
C4  72.9,12.5 180 top
C5  76.6,12.5 0 top
C6  18.25,77 180 top
C7  28,78.25 90 top
C8  33.5,81 90 top
C9  14,40.75 270 top
C10  18.5,38.5 270 top
C11  28.5,38.5 270 top
C12  38.5,37.25 180 top
C13  42,71 0 top
C14  58.25,59 180 top
C15  22.5,6.5 270 top
C16  46,8.5 270 top
C17  92.25,22.25 0 top
C18  81.25,33 180 top
C19  106.5,37.75 0 top
C20  104.75,33.5 180 top
C21  90.5,44.75 270 top
CON3  109.75,0.75 0 top
CON4  35.75,6 0 top
CON5  57,6 0 top
D1  100.25,12.25 270 top
D2  32,84.5 270 top
DRILEGEND  [DRILEGEND]  not placed on the board
GND_PAD  52.5,85.75 0 top
IC1  84.25,28.5 0 top
IC3  67.5,56 0 top
IC4  91,24.25 90 top
J1  24.33,26.76 0 top
J2  34.5,76.25 180 top
J3  24.33,62.32 0 top
J5  47.19,44.54 90 top
J6  103.5,59.5 0 top
J7  103.5,29.02 0 top
JP1  96,77.75 180 top
L1  82.5,11.75 90 top
L2  24.25,85.75 0 top
LED1  87,2.5 0 top
LED2  93.75,2.5 0 top
LED3  100.75,2.5 0 top
Q1  22.75,75.25 90 top
R1  106.25,14.25 0 top
R2  99.75,39 270 top
R3  27.25,74 180 top
R4  27.25,72.25 180 top
R5  28.75,85.75 180 top
R6  30.5,81.5 90 top
R7  14.75,36.5 270 top
R8  19.25,34.25 270 top
R9  30.2,34.75 270 top
R10  34.5,35.75 270 top
R11  13.25,36.5 270 top
R12  17.75,34.25 270 top
R13  28.66,34.75 270 top
R14  33,35.75 270 top
R15  25.5,2.75 90 top
R16  47.75,4.75 270 top
R17  85.75,6.75 90 top
R18  92.5,6.75 90 top
R19  99.5,6.5 90 top
R20  96.5,45.5 270 top
R21  98.25,35 90 top
R22  96.5,49.25 90 top
R23  104.5,65.5 90 top
R24  111.5,36.5 90 top
R25  106,65.5 90 top
R26  99.75,35 90 top
R27  96.75,35 90 top
R28  55.75,65 180 top
R29  97.25,22.5 90 top
R30  97.5,54 90 top
R31  102.75,23.25 90 top
R32  108.25,23.25 90 top
R33  100,65.5 270 top
R34  98.75,22.5 90 top
R35  98.5,65.5 270 top
R36  100.5,22.5 90 top
R37  100.25,54 90 top
R38  102.75,65.5 90 top
R42  106,52 90 top
R46  106.75,23.25 90 top
R47  104.5,52 90 top
R49  107.5,53 90 top
R50  103,52 90 top
R51  102.5,38.5 270 top
R52  101.25,35 270 top
R53  67.25,9.75 90 top
R54  45.75,4.75 270 top
R55  101.5,54 90 top
R56  104.25,23.25 270 top
R57  116.25,40.5 180 top
R59  110.5,53 90 top
R60  109,65.5 270 top
R61  107.5,65.5 270 top
U1  24.25,81.75 270 top
U2  39.25,76.25 180 top
U3  85.54,46.89 180 top
X2  74.75,-5.5 0 top

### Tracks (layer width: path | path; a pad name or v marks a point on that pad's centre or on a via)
1.8V  (via drill 0.6)
  Top 0.508: v22.5,10 22.5,8.5 | 22.5,8.5 C15.1 | C16.1 46,10.5 | 46,10.5 46,10.75 v45.25,11.5 | v52.75,41.5 51.5,42.75 51.5,46.25 49.75,48 49.75,64.5 v53.5,68.25 | v54.75,75 54.75,77 58.25,80.5 v65.5,80.5 | v69.75,82.75 78.25,82.75 79.49,81.51 JP1.33 | CON5.3 53.7,11.25 48.25,11.25 47.5,10.5 46,10.5 | CON4.3 32.45,11.25 27,11.25 24.25,8.5 22.5,8.5
  Route15 0.508: v51.5,23 51.5,18.25 47.75,14.5 45.25,14.5 43.75,13 | v22.5,10 24.75,12.25 28.25,12.25 30.75,9.75 40.5,9.75 43.75,13 | v45.25,11.5 43.75,13 | v50,36 50,33.38 J5.3
  Bottom 0.508: J5.3 48.43,30.57 51.5,27.5 v51.5,23 | v52.75,41.5 50,38.75 v50,36 | v53.5,68.25 53.5,73.75 v54.75,75 | v65.5,80.5 67.5,80.5 v69.75,82.75
5V  (via drill 0.6)
  Top 0.508: X2.1 70.14,9.11 69.25,10 69.25,11.25 70.35,12.35 C3.1 C2.1 70.35,16.4 v69.75,17 | R19.2 99.5,8.25 98,9.75 98,13.8 97.5,14.3 | v77.25,26 77.25,33 v80,35.75 | v81.75,44.25 81,44.25 79,46.25 79,48.75 81,50.75 81,55 82.75,56.75 87,56.75 88.25,58 88.25,65.75 87.5,66.5 v81.5,66.5
  Top 1.676: R1.P$1 102.5,14.25 102.45,14.3 D1.C 97.5,14.3 97.05,14.3 v97,14.25
  Route15 0.508: v69.75,17 69.75,21 67,23.75
  Route15 1.676: v97,14.25 96.75,14.25 | J1.1 J5.1 50.96,25.49 51,25.45
  Bottom 0.508: v80,35.75 81.75,37.5 v81.75,44.25 | v81.5,66.5 81.5,71.75 82.03,72.28 JP1.32
  pour Route15 (isolate 0.406): 102.25,26.75 102.25,11.25 84.5,11.25 84.5,23.25 50,23.25 50,26.75
BACKDOOR_NODE  (via drill 0.6)
  Top 0.203: IC3.3 v64.33,44.58 | v65,41.75 66.25,41.75 67.95,43.45 69.55,43.45 75.5,37.5 88.75,37.5 v89.75,36.5 | v90.5,40 97,40 101.5,44.5 R55.1
  Bottom 0.203: v64.33,44.58 64.33,42.42 v65,41.75 | v89.75,36.5 89.75,39.25 v90.5,40
BACKDOOR_SUP  (via drill 0.6)
  Top 0.203: J3.13 25.5,62.22 25.5,65.75 26.5,66.75 47,66.75 52,71.75 64,71.75 v64.5,71.25 | v64.5,65.5 65.59,64.41 IC3.17
  Bottom 0.203: v64.5,71.25 v64.5,65.5
BATT
  Top 0.508: 18.75,79.75 18.75,82.25 19.75,83.25 21.5,83.25 22.05,82.7 U1.1 22.98,82.72 L2.1 | U1.3 21.8,80.8 20.75,79.75 18.75,79.75 | 18.75,79.75 18.75,78.5 19.1,78.15 C6.1 19.1,76.15 20,75.25 Q1.3
BUF_EN  (via drill 0.6)
  Top 0.203: IC3.1 61.78,55.53 63.05,56.8 IC3.19 63.05,63.94 62.5,64.5 v62.5,65.5 | J3.12 26.87,65.37 27.75,66.25 47.25,66.25 52.25,71.25 62,71.25 v62.5,70.75 | R28.1 56.6,66.1 v57.25,66.75
  Bottom 0.203: v62.5,70.75 62.5,66.75 | 62.5,66.75 v62.5,65.5 | v57.25,66.75 62.5,66.75
COUNTER
  Top 0.508: U1.5 25.52,82.72 L2.2 R5.2
DIO_0
  Top 0.203: J6.3 107.94,63.2 108.25,63.5 108.75,63.5 109,63.75 R60.2
DIO_1
  Top 0.203: J6.5 106.67,63.17 107,63.5 107.25,63.5 107.5,63.75 R61.2
DIO_7
  Top 0.203: J6.2 109.22,55.78 109.5,55.5 110,55.5 110.5,55 R59.2
DIO_12
  Top 0.203: J6.12 102.86,55.13 103,55 R50.2
DIO_15
  Top 0.203: J6.6 106.67,55.83 107.5,55 R49.2
DIO_21
  Top 0.203: J7.18 99.06,25.3 98.25,24.5 97.5,24.5 97.25,24.25 R29.2
DIO_23
  Top 0.203: J7.5 106.67,34.92 107.5,35.75 109,35.75 109.75,36.5 109.75,39.25 111,40.5 R57.2
DIO_24
  Top 0.203: J7.10 104.14,25.36 104.25,25.25 R56.1
DIO_25
  Top 0.203: J7.11 102.86,32.63 102.5,33 R51.2
DIO_26
  Top 0.203: J7.6 106.67,25.32 106.75,25.25 R46.2
DIO_27
  Top 0.203: J7.13 101.59,32.66 101.25,33 R52.2
DIO_30
  Top 0.203: J7.12 102.86,25.36 102.75,25.25 R31.2
GND  (via drill 0.6)
  Top 0.203: 83.75,32.5 83.6,32.35 IC1.12 | IC1.9 85.55,32.05 85.75,32.25 87.25,32.25 87.5,32 | IC4.3 91.85,25.35
  Top 0.406: U3.5 83.37,48.37
  Top 0.508: U1.2 v20.5,81.75 | IC1.7 86.83,25.57 87,25.75
  other vias: 114.75,32.75 96,42 90.5,48 103.75,35.25 107.75,39.75 35.75,2.75 47,1.5 20,86 123.25,67.25 114,58 108.5,34.5 103,45.25 23.25,70 12.5,70 15.75,66.5 16.5,58.25 20.25,55.25 23.75,57.5 29.25,53 35.25,55.25 54.5,51.75 79.75,60 69.45,41.05 55.25,45.75 92.75,64.75 57,60.75 78.5,29 94.5,25.75 92,29 55.25,28.75 68.25,37.75 68,25.5 87.75,26.25 21.75,66.5 63.25,78.25 81.75,82.5 85.75,53 57,2.75
  pour Top (isolate 0.406, no thermals): -6,93.5 148.75,93.5 148.75,-11 -6,-11
  pour Route2 (isolate 0.406, no thermals): -6.75,94.75 153.75,94.75 153.75,-12 -6.75,-12
  pour Bottom (isolate 0.406, no thermals): -10.25,95.5 161.25,95.5 161.25,-17.75 -10.25,-17.75
I2C_SCLK  (via drill 0.6)
  Top 0.203: v38.5,70.5 38.5,71.5 38.62,71.61 U2.6
  Bottom 0.203: J3.4 38.5,65.06 v38.5,70.5
I2C_SD  (via drill 0.6)
  Top 0.203: v36,70.5 37.34,71.84 U2.5
  Bottom 0.203: J3.3 35.75,62.33 35.75,64.75 36,65 v36,70.5
JTAG_TCK_NODE  (via drill 0.6)
  Top 0.203: R24.2 v111.5,39 | v94.75,50 91.5,53.25 91.5,68.75 90.25,70 79.25,70 78.25,69 v72,69 | v72,63.25 72,62.5 71.94,62.45 IC3.12
  Bottom 0.203: v111.5,39 111.5,40.75 109,43.25 96,43.25 94.75,44.5 v94.75,50 | v72,69 v72,63.25
JTAG_TCK_SUP  (via drill 0.6)
  Top 0.203: v26.75,56 24,53.25 24,50 25,49 34.75,49 39.25,44.5 48,44.5 49.5,43 49.5,41.5 51.25,39.75 52,39.75 53.75,38 57.75,38 61.5,41.75 v61.5,44.5 | v70.75,48.25 70.75,49.05 70.67,49.12 IC3.8
  Bottom 0.203: v70.75,48.25 70,48.25 69,49.25 62.75,49.25 61.5,48 v61.5,44.5 | J3.8 30.75,62.39 30.75,60 v26.75,56
JTAG_TDI_NODE
  Top 0.203: R21.2 98.25,37.5 97.25,38.5 78.25,38.5 71.94,44.8 IC3.9
JTAG_TDI_SUP  (via drill 0.6)
  Top 0.203: J3.9 30.75,62.39 30.75,64.25 31.75,65.25 47.75,65.25 52.75,70.25 60.75,70.25 61.75,69.25 65.5,69.25 66,69.75 68.75,69.75 70.25,71.25 72.75,71.25 v73.25,70.75 | v73.25,64.75 73.25,63.75 73.22,63.72 IC3.11
  Bottom 0.203: v73.25,70.75 v73.25,64.75
JTAG_TDO  (via drill 0.6)
  Top 0.203: R27.2 94.4,35.85 v93.25,37 | v90.75,34.5 90.25,35 87.75,35 85.75,37 75.25,37 72.5,39.75 64.75,39.75 v64,40.5 | v60,42.5 60,41 57.5,38.5 54,38.5 50.75,41.75 50.75,44.75 48.5,47 46.25,47 35.75,57.5 35.75,62.33 J3.6
  Bottom 0.203: v93.25,37 v90.75,34.5 | v64,40.5 62,42.5 v60,42.5
JTAG_TMS_NODE  (via drill 0.6)
  Top 0.203: IC3.7 69.41,46.59 78,38 89.75,38 96.75,31 v96.75,25.5 | R32.1 v108.25,20.75
  Bottom 0.203: v108.25,20.75 107.25,20.75 102.5,25.5 v96.75,25.5
JTAG_TMS_SUP  (via drill 0.6)
  Top 0.203: v37.25,59.25 41.25,59.25 43.25,61.25 43.25,63 45,64.75 48,64.75 53,69.75 60.5,69.75 61.5,68.75 69.5,68.75 v70.75,70 | v70.75,63.75 70.75,63 70.67,62.92 IC3.13
  Bottom 0.203: J3.7 33.75,59.25 v37.25,59.25 | v70.75,70 v70.75,63.75
LINK0  (via drill 0.6)
  Top 0.203: v3.25,30 3.25,24.25 7.75,19.75 9.5,19.75 20,9.25 20,4.75 21.15,3.6 R15.2 43.1,3.6 44,4.5 44,5.25 44.35,5.6 R54.1 | v17,52.25 18,53.25 18,62.34 J3.18
  Bottom 0.203: v3.25,30 4.75,31.5 10.25,31.5 13,34.25 13,43.25 15.25,45.5 15.25,50.5 v17,52.25
LINK4  (via drill 0.6)
  Top 0.203: 57,6.25 54.5,3.75 50.25,3.75 49,5 49,5.25 48.65,5.6 R16.1 | 57.01,6.25 57,6.25 | 57,6.25 57,8.5 59,10.5 62.75,10.5 63.75,11.5 | 63.75,11.5 v63.75,17.5 | v63.75,24.45 63.75,25.25 57,32 45.5,32 43.5,34 43.5,35.75 33,46.25 14,46.25 v13.5,46.75 | v14.75,55 13,56.75 13,62.42 J3.22 | R53.2 66.4,10.6 65.5,11.5 63.75,11.5
  Bottom 0.203: v63.75,17.5 v63.75,24.45 | v13.5,46.75 12,48.25 12,50.5 14.75,53.25 v14.75,55
N$1
  Top 0.203: CON4.AG 41.12,2.5 45.25,2.5 45.75,3 R54.2
N$2
  Top 0.203: R3.2 25.5,74 25.2,74.3 Q1.1
N$3
  Top 0.203: R14.1 R10.1 36.1,36.6 36.75,37.25 C12.2
N$4
  Top 0.203: R13.1 R9.1 30.2,36.8 29.35,37.65 C11.2
N$5
  cutout Top (isolate 0.406, no thermals): 15.5,71.25 arc90 18.25,68.5 18.5,68.5 arc90 21.5,71.5 arc90 18.5,74.5 arc95
N$6
  cutout Route2 (isolate 0.406, no thermals): 18.5,74.5 arc-90 21.5,71.5 arc-90 18.5,68.5 arc-90 15.5,71.5 arc-90
N$7
  cutout Route15 (isolate 0.406, no thermals): 18.5,74.5 arc-90 21.5,71.5 arc-90 18.5,68.5 arc-90 15.5,71.5 arc-90
N$8
  cutout Bottom (isolate 0.406, no thermals): 18.5,74.5 arc-90 21.5,71.5 arc-90 18.5,68.5 arc-90 15.5,71.5 arc-90
N$9
  cutout Top (isolate 0.406, no thermals): 119.5,71.25 arc90 122.25,68.5 122.5,68.5 arc90 125.5,71.5 arc90 122.5,74.5 arc95
N$10
  cutout Route2 (isolate 0.406, no thermals): 122.5,74.5 arc-90 125.5,71.5 arc-90 122.5,68.5 arc-90 119.5,71.5 arc-90
N$11
  cutout Route15 (isolate 0.406, no thermals): 122.5,74.5 arc-90 125.5,71.5 arc-90 122.5,68.5 arc-90 119.5,71.5 arc-90
N$12
  cutout Bottom (isolate 0.406, no thermals): 122.5,74.5 arc-90 125.5,71.5 arc-90 122.5,68.5 arc-90 119.5,71.5 arc-90
N$13
  Top 0.203: R16.2 47.75,2.25 48.8,1.2 CON5.AY
N$14
  Top 0.508: X2.S1 X2.S2 81.32,7.32 82.5,8.5 L1.1
N$15
  Top 0.203: J7.4 107.94,25.3 108.25,25 R32.2
N$16
  cutout Top (isolate 0.406, no thermals): 119.5,17.25 arc90 122.25,14.5 122.5,14.5 arc90 125.5,17.5 arc90 122.5,20.5 arc95
N$17
  cutout Route2 (isolate 0.406, no thermals): 122.5,20.5 arc-90 125.5,17.5 arc-90 122.5,14.5 arc-90 119.5,17.5 arc-90
N$18
  Top 0.203: J7.1 109.22,32.72 110,33.5 110.75,33.5 111.5,34.25 R24.1
N$19
  Top 0.203: R8.1 R12.1 17.75,35.75 18.5,36.5 C10.2
N$20
  Top 0.203: J7.15 100.33,32.67 99.75,33.25 R26.1
N$21
  Top 0.203: R7.1 R11.1 13.25,38 14,38.75 C9.2
N$22
  Top 0.203: J7.17 99.06,32.7 98.75,33 98.5,33 98.25,33.25 R21.1
N$23
  Top 0.203: J7.19 97.78,32.72 97.5,33 97,33 96.75,33.25 R27.1
N$24
  Top 0.203: J6.7 105.41,63.16 106,63.75 R25.1
N$25
  Top 0.203: J6.9 104.14,63.13 104.5,63.5 R23.1
N$26
  Top 0.203: R29.1 97.25,19.75 99.25,17.75 110,17.75 111.25,19 111.25,23.5 123.25,35.5 123.25,63.5 118.75,68 118.75,72.75 122,76 122,77.15 JP1.1
N$27
  Top 0.203: R15.1 25.5,1.25 25.75,1 27.25,1 27.45,1.2 CON4.AY
N$28
  Top 0.203: J6.20 97.75,57.44 97.75,56 97.5,55.75 R30.2
N$29
  Top 0.203: LED1.A 85.73,4.73 85.75,4.75 R17.1
N$30
  Top 0.203: LED2.A 92.48,4.73 92.5,4.75 R18.1
N$31
  Top 0.203: R55.2 101.5,55.75 101.59,55.84 J6.14
N$32
  Top 1.676: R1.P$2 C1.+ 114.5,10.25 112.35,8.1 CON3.1
N$33
  Top 0.203: CON5.AG 67.25,7.38 R53.1
N$34
  Top 0.203: R6.1 31.85,80.65 32.35,80.15 C8.1 35.65,80.15 36.5,81 38.25,81 38.62,80.64 U2.3
N$35
  Top 0.203: J6.15 100.33,63.17 100,63.5 R33.2
N$36
  Top 0.203: R31.1 102.75,20.25 104.75,18.25 109.5,18.25 110.75,19.5 110.75,23.75 122.75,35.75 122.75,63.25 118.25,67.75 118.25,73 120.13,74.88 JP1.2
N$37
  Top 0.203: R56.2 104.25,19.5 105,18.75 109,18.75 110.25,20 110.25,24 122.25,36 122.25,63 117.75,67.5 117.75,73.25 118.85,74.35 118.85,77.76 JP1.3
N$38
  Top 0.203: J6.17 99.06,63.2 98.5,63.75 R35.2
N$40
  Top 0.203: R46.1 106.75,20.25 107.5,19.5 108.75,19.5 109.75,20.5 109.75,24.25 121.75,36.25 121.75,62.75 117.25,67.25 117.25,73.5 117.59,73.84 JP1.4
N$41
  Top 0.203: R57.1 118.75,40.5 121.25,43 121.25,62.5 116.75,67 116.75,71.25 116.25,71.75 116.25,77.82 JP1.5
N$42
  Top 0.203: R51.1 102.5,40.5 103.75,41.75 119.25,41.75 120.75,43.25 120.75,62.25 116.25,66.75 116.25,71 115.05,72.2 JP1.6
N$43
  Top 0.203: R52.1 101.25,41 102.5,42.25 119,42.25 120.25,43.5 120.25,62 114.5,67.75 114.5,70.25 113.75,71 113.75,77.78 JP1.7
N$44
  Top 0.203: R50.1 103,49.25 106.25,46 106.25,45 108.5,42.75 118.75,42.75 119.75,43.75 119.75,61.75 114,67.5 114,70 112.51,71.49 JP1.8
N$45
  Top 0.203: R47.1 104.5,49 107,46.5 107,45.25 109,43.25 118.5,43.25 119.25,44 119.25,61.5 113.5,67.25 113.5,69.75 111.25,72 111.25,77.74 JP1.9
N$46
  Top 0.203: R42.1 106,48.75 107.75,47 107.75,45.5 109.5,43.75 118,43.75 118.75,44.5 118.75,61.25 113,67 113,69.5 109.97,72.53 JP1.10
N$47
  Top 0.203: R49.1 107.5,48.25 111.5,44.25 117.5,44.25 118.25,45 118.25,61 112.5,66.75 112.5,69.25 108.75,73 108.75,77.7 JP1.11
N$49
  Top 0.203: U3.2 U3.3
N$50
  Top 0.203: R19.1 99.5,4.5 99.48,4.48 LED3.A
N$51
  cutout Route15 (isolate 0.406, no thermals): 122.5,20.5 arc-90 125.5,17.5 arc-90 122.5,14.5 arc-90 119.5,17.5 arc-90
N$52
  cutout Bottom (isolate 0.406, no thermals): 122.5,20.5 arc-90 125.5,17.5 arc-90 122.5,14.5 arc-90 119.5,17.5 arc-90
N$53
  cutout Top (isolate 0.406, no thermals): 15.5,17.25 arc90 18.25,14.5 18.5,14.5 arc90 21.5,17.5 arc90 18.5,20.5 arc95
N$54
  cutout Route2 (isolate 0.406, no thermals): 18.5,20.5 arc-90 21.5,17.5 arc-90 18.5,14.5 arc-90 15.5,17.5 arc-90
N$55
  cutout Route15 (isolate 0.406, no thermals): 18.5,20.5 arc-90 21.5,17.5 arc-90 18.5,14.5 arc-90 15.5,17.5 arc-90
N$56
  cutout Bottom (isolate 0.406, no thermals): 18.5,20.5 arc-90 21.5,17.5 arc-90 18.5,14.5 arc-90 15.5,17.5 arc-90
N$57
  cutout Top (isolate 0.406): -0.5,58.5 10.5,58.5 10.5,33.5 -0.5,33.5
N$58
  cutout Route2 (isolate 0.406): -0.5,58.5 10.5,58.5 10.5,33.5 -0.5,33.5
N$59
  cutout Route15 (isolate 0.406): -0.5,58.5 10.5,58.5 10.5,33.5 -0.5,33.5
N$60
  cutout Bottom (isolate 0.406): -0.5,58.5 10.5,58.5 10.5,33.5 -0.5,33.5
N$61
  cutout Top (isolate 0.406): 124.5,93.75 140.5,93.75 140.5,-6 124.5,-6
N$62
  cutout Route2 (isolate 0.406): 124.5,93.75 140.5,93.75 140.5,-6 124.5,-6
N$63
  cutout Route15 (isolate 0.406): 124.5,93.75 140.5,93.75 140.5,-6 124.5,-6
N$64
  cutout Bottom (isolate 0.406): 124.5,93.75 140.5,93.75 140.5,-6 124.5,-6
N$65
  Top 0.203: R59.1 110.5,47.25 112.5,45.25 116.5,45.25 117.25,46 117.25,60.5 111.5,66.25 111.5,68.75 106.1,74.15 106.1,77.81 JP1.13
N$66
  Top 0.203: R36.2 100.5,24.5 100.75,24.75 101.25,24.75 101.59,25.09 J7.14
N$67
  Top 0.203: R34.2 98.75,24.25 99.25,24.75 99.75,24.75 100.33,25.32 J7.16
N$68
  Top 0.203: R60.1 109,68.75 104.89,72.86 JP1.14
N$69
  Top 0.203: R61.1 107.5,69 103.6,72.9 103.6,77.77 JP1.15
N$72
  Top 0.203: J6.11 102.86,63.38 102.75,63.5 R38.1
NODE_LED  (via drill 0.6)
  Top 0.203: J7.8 105.41,24.59 105.75,24.25 105.75,20.5 v105.25,20 | R18.2 92.5,15 94.5,17 v97,17
  Bottom 0.203: v105.25,20 103.25,20 101.75,18.5 98.5,18.5 v97,17
NODE_POWER  (via drill 0.6)
  Top 0.203: v32.5,69.75 29.75,69.75 28.1,71.4 R4.1 R3.1
  Bottom 0.203: v32.5,69.75 32.5,66 33.25,65.25 33.25,62.29 J3.5
NRESET_NODE  (via drill 0.6)
  Top 0.203: R26.2 R2.2 98.35,38.15 97.5,39 84,39 | 84,39 79.5,39 v78.75,39.75 | IC3.5 66.86,46.88 68.5,45.25 69.25,45.25 v71.2,43.3 | IC4.2 92.5,24.25 93.25,25 93.25,30 88.75,34.5 87.5,34.5 86.5,35.5 v84.75,35.5 | v84.75,40.75 84,40 84,39
  Bottom 0.203: v78.75,39.75 74.75,39.75 v71.2,43.3 | v84.75,35.5 v84.75,40.75
NRESET_SUP  (via drill 0.6)
  Top 0.203: J3.10 31.57,65.75 47.5,65.75 52.5,70.75 61,70.75 62,69.75 65.25,69.75 v66.75,71.25 | v68.25,63.75 68.25,63 68.14,62.88 IC3.15
  Bottom 0.203: v66.75,71.25 66.75,66 68.25,64.5 v68.25,63.75
RESET_NODE  (via drill 0.6)
  Top 0.203: IC4.4 88.4,24.9 v87.75,24.25 | v82.25,23.5 82.25,24.5 82.3,24.55 IC1.1 | IC1.4 84.25,22.75 v83.5,22
  Bottom 0.203: v87.75,24.25 87.25,24.75 86,24.75 84.75,23.5 | 84.75,23.5 v82.25,23.5 | v83.5,22 84.25,22 84.75,22.5 84.75,23.5
RX0_N
  Top 0.203: R8.2 19.25,32.05 18.7,31.5 18.7,30.67 17.83,29.8 13.83,29.8 13.1,29.07 13.1,26.56 J1.21
  Bottom 0.203: J1.21 13.1,24.42 13.1,23.68 13.58,23.2 24.83,23.2 29.58,18.45 37.83,18.45 39.3,16.98 39.3,16.08 CON4.8
RX0_P
  Top 0.203: R12.2 17.75,32.05 18.3,31.5 18.3,30.83 17.67,30.2 13.67,30.2 12.7,29.23 12.7,26.55 J1.23
  Bottom 0.203: J1.23 12.7,24.42 12.7,23.52 13.42,22.8 24.67,22.8 29.42,18.05 37.67,18.05 38.9,16.82 38.9,12.68 CON4.7
RX4_N
  Top 0.203: J1.5 33.42,26.56 33.42,30.89 33.95,31.42 33.95,33 34.5,33.55 R10.2
  Bottom 0.203: J1.5 33.4,24.4 33.4,22.63 34.33,21.7 39.08,21.7 41.83,18.95 59.08,18.95 60.6,17.43 60.6,16.03 CON5.8
RX4_P
  Top 0.203: J1.7 33.02,26.55 33.02,31.05 33.55,31.58 33.55,33 33,33.55 R14.2
  Bottom 0.203: J1.7 33,24.44 33,22.47 34.17,21.3 38.92,21.3 41.67,18.55 58.92,18.55 60.2,17.27 60.2,12.67 CON5.7
SSI_CLK
  Top 0.203: J6.16 100.33,55.83 100.25,55.75 R37.2
TMP_POWER  (via drill 0.6)
  Top 0.406: U3.1 89.08,45.91 89.4,45.6 C21.1
  Top 0.508: J6.4 107.94,55.8 108.75,55 v108.75,50.75 | v99.75,45 98.5,45 98.15,44.65 R20.2 92.85,44.65 91.9,45.6 C21.1 | R22.2 99.65,50.1 v100.25,49.5
  Route15 0.508: v108.75,50.75 105.5,47.5 102.25,47.5 | 102.25,47.5 v99.75,45 | 102.25,47.5 v100.25,49.5
TMP_SCL  (via drill 0.6)
  Top 0.203: U3.8 80.83,45.91 80.25,46.5 80.25,48 82.75,50.5 91,50.5 93.1,48.4 R22.1 97.85,48.4 98.25,48 v100,48 | J6.10 104.14,55.37 v104.5,55 R47.2
  Bottom 0.203: v100,48 104.5,52.5 v104.5,55
TMP_SDA  (via drill 0.6)
  Top 0.203: U3.7 81.19,46.56 80.75,47 80.75,47.75 83,50 90.75,50 94.4,46.35 R20.1 97.85,46.35 98.25,46.75 v99,46.75 | J6.8 105.41,55.59 v106,55 R42.2
  Bottom 0.203: v99,46.75 105.5,46.75 106,47.25 v106,55
TX0_N
  Top 0.203: R7.2 14.75,34.5 14.2,33.95 14.2,33.17 10.45,29.42 10.45,29.21 J1.24 10.57,26.97 10.57,23.68 11.05,23.2 22.83,23.2 30.83,15.2 32.56,15.2 CON4.2
TX0_P
  Top 0.203: R11.2 13.25,34.5 13.8,33.95 13.8,33.33 10.05,29.58 10.05,28.98 J1.26 10.17,26.95 10.17,23.52 10.89,22.8 22.67,22.8 31.3,14.16 CON4.1
TX4_N
  Top 0.203: R9.2 30.2,32.5 29.7,32 29.7,31.08 30.7,30.08 30.7,29.28 J1.8 30.89,26.97 30.89,22.89 32.83,20.95 41.83,20.95 46.83,15.95 51.33,15.95 52.1,15.19 CON5.2
TX4_P
  Top 0.203: R13.2 28.66,32.63 29.3,32 29.3,30.92 30.3,29.92 30.3,28.91 J1.10 30.49,26.95 30.49,22.73 32.67,20.55 41.67,20.55 46.67,15.55 51.17,15.55 52.55,14.16 CON5.1
UARTB_RXD/TXD_NODE  (via drill 0.6)
  Top 0.203: R34.1 v98.75,20.25 | IC1.5 84.9,23.6 89.25,19.25 94.75,19.25 v95.75,20.25
  Bottom 0.203: v98.75,20.25 v95.75,20.25
UARTB_RXD/TXD_SUP  (via drill 0.6)
  Top 0.203: J3.25 11,59.14 11,52.5 16.5,47 33,47 45.5,34.5 61.75,34.5 | 61.75,34.5 65,34.5 79.25,20.25 83.25,20.25 v84.5,19 | v86.5,23.75 85.55,24.7 IC1.6 | JP1.38 72.93,75 v57.5,75 | v57.5,68.75 59.25,67 59.25,64 57.75,62.5 56.5,62.5 54.5,60.5 54.5,57.5 60.25,51.75 60.25,45.5 58.25,43.5 v58.25,41.75 | v61.75,38.25 61.75,34.5
  Bottom 0.203: v57.5,75 v57.5,68.75 | v58.25,41.75 v61.75,38.25 | v86.5,23.75 86.5,21 v84.5,19
UARTB_TXD/RXD_NODE  (via drill 0.6)
  Top 0.203: v95.75,22 95.75,31.25 91.5,35.5 89,35.5 v88,36.5 | v88,40 89,41 92.5,41 v94.25,42.75 | v90.5,52.75 90.5,68 89.25,69.25 80.25,69.25 v79.5,68.5 | v77,64.5 75,66.5 70.75,66.5 69.5,65.25 67.5,65.25 66.86,64.61 IC3.16 | R36.1 100.5,20.75 v101.25,20
  Bottom 0.203: v101.25,20 99.25,22 v95.75,22 | v88,36.5 v88,40 | v94.25,42.75 94.25,49 v90.5,52.75 | v79.5,68.5 79.5,67 v77,64.5
UARTB_TXD/RXD_SUP  (via drill 0.51, 0.6)
  Top 0.203: J3.23 11.63,52.87 17,47.5 33.5,47.5 44,37 58.25,37 65.59,44.34 IC3.4 65.59,52.84 67.05,54.3 73.85,54.3 75.4,52.75 v75.4,51.05 | v59.75,68.75 60.25,68.25 71.5,68.25 71.75,68 72.25,68 72.5,68.25 78.25,68.25 81.25,65.25 82.25,65.25 82.5,65.5 87,65.5 87.5,65 87.5,58.5 86.5,57.5 82.25,57.5 80.2,55.45 80.2,51.9 v79.35,51.05 | JP1.40 62.77,76.48 62.75,76.5 v59.75,76.5
  Bottom 0.203: v59.75,68.75 v59.75,76.5 | v79.35,51.05 v75.4,51.05
UARTF_CTS_N/RTS_N  (via drill 0.6)
  Top 0.203: J3.11 v38.42,49.5 | v51.25,49.5 56.5,49.5 v58.5,51.5 | v82.75,51.5 87.5,51.5 89.5,53.5 v89.5,55 | R30.1 96.35,53.15 94.5,55 v93.5,55 93.5,56.25 94.75,57.5 94.75,69.25 v93.5,70.5
  Bottom 0.203: v38.42,49.5 v51.25,49.5 | v82.75,51.5 81.25,53 60,53 v58.5,51.5 | v89.5,55 v93.5,55 | v93.5,70.5 93.5,75.17 JP1.24
UARTF_RTS_N/CTS_N_NODE  (via drill 0.6)
  Top 0.203: v93.25,68.75 91,71 76,71 v75.25,70.25 | v75.25,64.75 74,66 71.25,66 69.41,64.16 IC3.14 | R38.2 102.75,69 v101.5,70.25
  Bottom 0.203: v75.25,70.25 v75.25,64.75 | v101.5,70.25 95.5,70.25 94,68.75 v93.25,68.75
UARTF_RTS_N/CTS_N_SUP  (via drill 0.51, 0.6)
  Top 0.203: J3.15 21.79,51.21 24.5,48.5 34.25,48.5 40.75,42 48.25,42 v51.75,38.5 | v67,45 57.75,35.75 v54.5,35.75 | v68.25,47.5 68.25,48.25 68.14,48.37 IC3.6 68.14,53.23 68.6,53.7 73.15,53.7 74.15,52.7 74.15,50.85 75.2,49.8 76.7,49.8 79.75,52.85 79.75,55.65 82.05,57.95 85.6,57.95 86.5,58.85 86.5,63.5 v85.9,64.1
  Bottom 0.203: v51.75,38.5 v54.5,35.75 | v67,45 68.25,46.25 v68.25,47.5 | v85.9,64.1 85.9,67.55 89.65,71.3 JP1.26
UARTF_RXD/TXD_NODE  (via drill 0.6)
  Top 0.203: IC1.2 82.95,26.95 84,28 v88.25,28 | v110.5,28 112.75,28 120.25,35.5 v120.25,39.25 | v115.75,46.75 115.75,48.5 116.75,49.5 116.75,60 113.75,63 112.25,63 v111,64.25 | v102,73 104.5,70.5 R23.2
  Bottom 0.203: v88.25,28 v110.5,28 | v120.25,39.25 120.25,42.25 v115.75,46.75 | v111,64.25 111,68 106,73 v102,73
UARTF_RXD/TXD_SUP  (via drill 0.6)
  Top 0.203: J3.26 10.75,65.25 14.75,65.25 15.5,64.5 | 15.5,64.5 15.5,57 v16.75,55.75 | v19,45 20,45 20.75,45.75 32.5,45.75 42.75,35.5 42.75,33 45,30.75 45,30 45.75,29.25 49.75,29.25 55.75,23.25 71.5,23.25 v72.5,24.25 | v77.25,24.25 79,24.25 81.25,22 82.25,22 83.6,23.35 IC1.3 | v67,84.75 82.25,84.75 85.85,81.15 85.85,77.74 JP1.28 | v63.25,83.25 58.75,83.25 v51.5,76 | v49.5,72.75 49.5,71.5 46.25,68.25 21.25,68.25 20.25,67.25 18.25,67.25 15.5,64.5
  Bottom 0.203: v16.75,55.75 19,53.5 v19,45 | v72.5,24.25 v77.25,24.25 | v67,84.75 65.5,83.25 v63.25,83.25 | v51.5,76 49.5,74 v49.5,72.75
UARTF_TXD/RXD_NODE  (via drill 0.6)
  Top 0.203: v97,71.25 95.25,71.25 94.75,71.75 68.75,71.75 68.25,71.25 v68.25,70.75 | v68.25,66.25 66.75,66.25 66.5,66.5 64,66.5 63.5,66 63.5,65 64.33,64.17 IC3.18 | v106,68.5 R25.2
  Bottom 0.203: v68.25,70.75 v68.25,66.25 | v97,71.25 102,71.25 104.75,68.5 v106,68.5
UARTF_TXD/RXD_SUP  (via drill 0.6)
  Top 0.203: v13.25,53.75 19,48 34,48 42.5,39.5 49.5,39.5 51.5,37.5 58,37.5 63.05,42.55 IC3.2 63.05,53.8 64,54.75 v74.75,54.75 | v83.25,68 88.75,68 89.75,67 89.75,56.75 87.75,54.75 v83,54.75
  Bottom 0.203: J3.24 12.75,62.47 12.75,54.25 v13.25,53.75 | v83.25,68 83.25,75.16 JP1.30 | v83,54.75 v74.75,54.75
USB_PAD_N
  Top 0.203: X2.2 C4.1 73.75,13.2 74.55,14 74.55,17.17 71.42,20.3 70.55,20.3 70.25,20 68.5,20 68.25,20.25 66.75,20.25 66.5,20 65.25,20 65,20.25 63,20.25 62.75,20 61,20 60.75,20.25 49,20.25 48.75,20 47,20 46.75,20.25 45.21,20.25 42.8,22.67 42.8,23.7 42.65,23.85 42.65,25.25 42.8,25.4 42.8,26.35 42.65,26.5 42.65,27.85 42.8,28 42.8,30.67 40.92,32.55 39.4,32.55 39.15,32.3 37.55,32.3 37.3,32.55 36.58,32.55 35.95,31.92 35.95,29.11 J1.4
USB_PAD_P
  Top 0.203: X2.3 C5.1 75.75,13.2 74.95,14 74.95,17.33 71.58,20.7 45.33,20.7 43.2,22.83 43.2,30.83 41.08,32.95 36.42,32.95 35.55,32.08 35.55,29.08 J1.6
VCC  (via drill 0.6)
  Top 0.203: IC1.14 IC1.13 | IC1.10 84.9,32.15 85,32.25 v85,33.25
  Top 0.406: v82.5,34.5 82.1,34.1 C18.1 82.1,32.15 82.3,31.95 IC1.14
  Top 0.508: v41,69.5 41.15,69.65 C13.1 U2.8 | Q1.2 23.75,77.25 v22.75,78.25 | R6.2 29.6,82.35 v28.75,81.5 | v62.75,86.5 70.23,79.02 JP1.39 | R28.2 53.25,65 v52.5,64.25 | IC3.20 59.78,61.03 59.1,60.35 C14.1 59.1,56.85 v58.5,56.25 | IC4.5 89.1,23.6 88.75,23.25 88.75,22.5 89,22.25 C17.1 91.4,21.1 91.5,21 v92.25,21 | v86.72,33.25 88,33.25 90,31.25 v90,26
  Route15 0.406: v82.5,34.5 83.5,33.5 83.5,33.25
  Route15 0.508: v41,69.5 40.75,69.25 | v86.72,33.25 v85,33.25
  Route15 1.016: 60,35.25 68,35.25 70,33.25 83.5,33.25 v85,33.25 85.25,33.25
  Route15 1.422: J5.2 48.78,28.03 51.75,31
  Bottom 0.508: v90,26 89,25 89,21.25 89.25,21 v92.25,21
  pour Route15 (isolate 0.406): 17.25,35 50.75,35 50.75,30.25 61.25,30.25 61.25,71 30.5,71 30.5,84.25 64.5,84.25 64.5,89.75 -4.75,89.75 -4.75,30.25 17.25,30.25
VDD  (via drill 0.6)
  Top 0.508: J7.9 J7.7 105.41,32.41 105.6,32.6 C20.1 105.6,34.65 105.1,35.15 C19.1 105.1,39.85 v105.5,40.25 | U1.4 25.55,78.45 26.6,77.4 C7.1 28.85,77.4 30,76.25 J2.2 31.96,73.54 32.5,73 34,73 34.5,73.5 J2.1 | R37.1 100.25,52.25 v99.5,51.5
  pour Route15 (isolate 0.406): 33.5,82.25 67.5,82.25 67.5,89.75 120,89.75 120,30.25 66.5,30.25 66.5,75.25 33.5,75.25
VLED1
  Top 0.203: J3.16 25.95,67.75 46.5,67.75 51.5,72.75 98,72.75 100,70.75 R33.1
VLED2
  Top 0.203: J3.14 24.33,65.33 26.25,67.25 46.75,67.25 51.75,72.25 97.75,72.25 98.5,71.5 R35.1
VMEASURE  (via drill 0.6)
  Top 0.203: R5.1 30.5,85.75 30.6,85.65 D2.C 32.85,85.65 34.5,84 35.5,84 37.25,82.25 40.5,82.25 41.16,81.59 U2.1 46.15,78.85 51.25,73.75 75.75,73.75 76.25,74.25 v77.5,74.25 | v77.5,70 78,70.5 90.75,70.5 92,69.25 92,68.25 v93.25,67 | J6.13 101.59,68.41 v101,69
  Bottom 0.203: v77.5,70 v77.5,74.25 | v101,69 95.25,69 v93.25,67
WRT_STATUS  (via drill 0.6)
  Top 0.203: R17.2 85.75,15 81,19.75 79,19.75 66.75,32 v60,32
  Bottom 0.203: v60,32 16,32 14.25,30.25 8.5,30.25 6.75,28.5 6.75,26.25 7.51,25.49 J1.25

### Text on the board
tPlace: D21 | D30 | VCC | 1.8V | UART1 | GND | GND | D1 | D7 | D15 | SCL | D27 | D23 | D24 | CUT | BOTTOM | GND | TOP | 5V | RTS | CTS | GND | GND | D0 | D6 | SDA | D12 | D25 | D26 | JUNCTION | VDD | CherryMote v5 | University of Warsaw 2018 | 5V
tNames: UART2 | -> | <- | -> | <-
